VERSION 5.8 ;
BUSBITCHARS "[]" ;
DIVIDERCHAR "/" ;
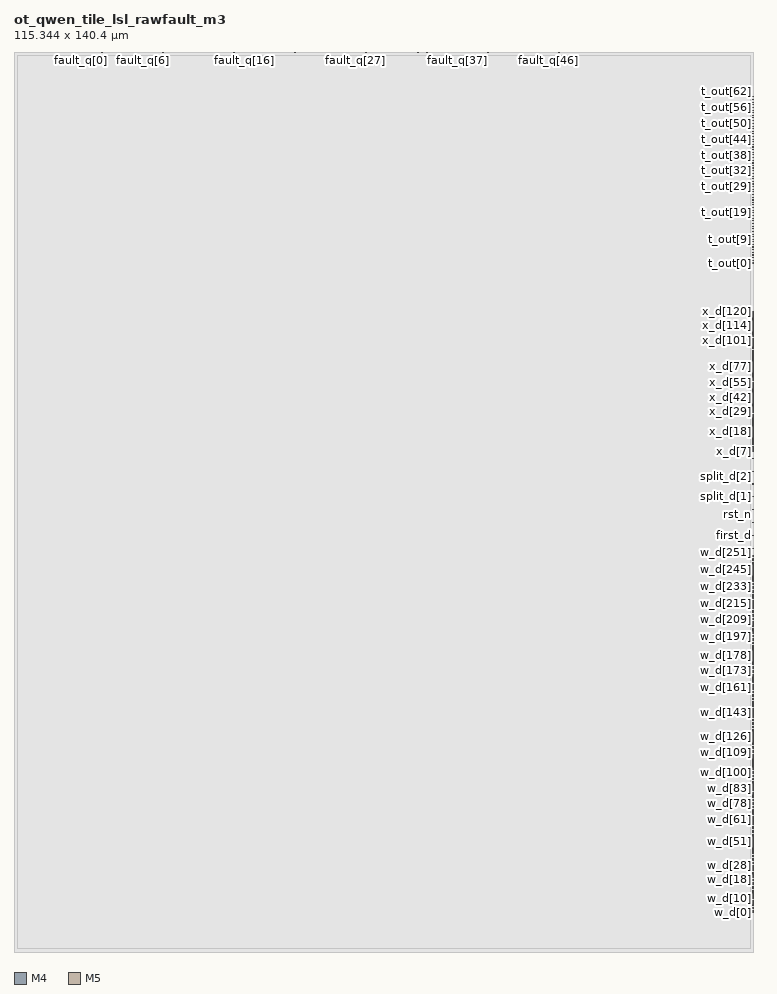
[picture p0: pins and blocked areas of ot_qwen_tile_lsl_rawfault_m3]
MACRO ot_qwen_tile_lsl_rawfault_m3
  CLASS BLOCK ;
  ORIGIN 0 0 ;
  SIZE 115.344 BY 140.4 ;
  SYMMETRY X Y ;
  PIN clk
    DIRECTION INPUT ;
    USE CLOCK ;
    PORT
      LAYER M4 ;
        RECT 115.2600 62.9760 115.3440 63.0000 ;
    END
  END clk
  PIN first_d
    DIRECTION INPUT ;
    USE SIGNAL ;
    PORT
      LAYER M4 ;
        RECT 115.2600 64.9920 115.3440 65.0160 ;
    END
  END first_d
  PIN rst_n
    DIRECTION INPUT ;
    USE SIGNAL ;
    PORT
      LAYER M4 ;
        RECT 115.2600 67.0080 115.3440 67.0320 ;
    END
  END rst_n
  PIN split_d[0]
    DIRECTION INPUT ;
    USE SIGNAL ;
    PORT
      LAYER M4 ;
        RECT 115.2600 68.9760 115.3440 69.0000 ;
    END
  END split_d[0]
  PIN split_d[1]
    DIRECTION INPUT ;
    USE SIGNAL ;
    PORT
      LAYER M4 ;
        RECT 115.2600 70.9920 115.3440 71.0160 ;
    END
  END split_d[1]
  PIN split_d[2]
    DIRECTION INPUT ;
    USE SIGNAL ;
    PORT
      LAYER M4 ;
        RECT 115.2600 73.0080 115.3440 73.0320 ;
    END
  END split_d[2]
  PIN split_d[3]
    DIRECTION INPUT ;
    USE SIGNAL ;
    PORT
      LAYER M4 ;
        RECT 115.2600 74.9760 115.3440 75.0000 ;
    END
  END split_d[3]
  PIN t_out[0]
    DIRECTION OUTPUT ;
    USE SIGNAL ;
    PORT
      LAYER M4 ;
        RECT 115.2600 107.4720 115.3440 107.4960 ;
    END
  END t_out[0]
  PIN t_out[10]
    DIRECTION OUTPUT ;
    USE SIGNAL ;
    PORT
      LAYER M4 ;
        RECT 115.2600 111.6000 115.3440 111.6240 ;
    END
  END t_out[10]
  PIN t_out[11]
    DIRECTION OUTPUT ;
    USE SIGNAL ;
    PORT
      LAYER M4 ;
        RECT 115.2600 111.9840 115.3440 112.0080 ;
    END
  END t_out[11]
  PIN t_out[12]
    DIRECTION OUTPUT ;
    USE SIGNAL ;
    PORT
      LAYER M4 ;
        RECT 115.2600 112.4160 115.3440 112.4400 ;
    END
  END t_out[12]
  PIN t_out[13]
    DIRECTION OUTPUT ;
    USE SIGNAL ;
    PORT
      LAYER M4 ;
        RECT 115.2600 112.8480 115.3440 112.8720 ;
    END
  END t_out[13]
  PIN t_out[14]
    DIRECTION OUTPUT ;
    USE SIGNAL ;
    PORT
      LAYER M4 ;
        RECT 115.2600 113.2320 115.3440 113.2560 ;
    END
  END t_out[14]
  PIN t_out[15]
    DIRECTION OUTPUT ;
    USE SIGNAL ;
    PORT
      LAYER M4 ;
        RECT 115.2600 113.6640 115.3440 113.6880 ;
    END
  END t_out[15]
  PIN t_out[16]
    DIRECTION OUTPUT ;
    USE SIGNAL ;
    PORT
      LAYER M4 ;
        RECT 115.2600 114.0480 115.3440 114.0720 ;
    END
  END t_out[16]
  PIN t_out[17]
    DIRECTION OUTPUT ;
    USE SIGNAL ;
    PORT
      LAYER M4 ;
        RECT 115.2600 114.4800 115.3440 114.5040 ;
    END
  END t_out[17]
  PIN t_out[18]
    DIRECTION OUTPUT ;
    USE SIGNAL ;
    PORT
      LAYER M4 ;
        RECT 115.2600 114.8640 115.3440 114.8880 ;
    END
  END t_out[18]
  PIN t_out[19]
    DIRECTION OUTPUT ;
    USE SIGNAL ;
    PORT
      LAYER M4 ;
        RECT 115.2600 115.2960 115.3440 115.3200 ;
    END
  END t_out[19]
  PIN t_out[1]
    DIRECTION OUTPUT ;
    USE SIGNAL ;
    PORT
      LAYER M4 ;
        RECT 115.2600 107.9040 115.3440 107.9280 ;
    END
  END t_out[1]
  PIN t_out[20]
    DIRECTION OUTPUT ;
    USE SIGNAL ;
    PORT
      LAYER M4 ;
        RECT 115.2600 115.6800 115.3440 115.7040 ;
    END
  END t_out[20]
  PIN t_out[21]
    DIRECTION OUTPUT ;
    USE SIGNAL ;
    PORT
      LAYER M4 ;
        RECT 115.2600 116.1120 115.3440 116.1360 ;
    END
  END t_out[21]
  PIN t_out[22]
    DIRECTION OUTPUT ;
    USE SIGNAL ;
    PORT
      LAYER M4 ;
        RECT 115.2600 116.5440 115.3440 116.5680 ;
    END
  END t_out[22]
  PIN t_out[23]
    DIRECTION OUTPUT ;
    USE SIGNAL ;
    PORT
      LAYER M4 ;
        RECT 115.2600 116.9280 115.3440 116.9520 ;
    END
  END t_out[23]
  PIN t_out[24]
    DIRECTION OUTPUT ;
    USE SIGNAL ;
    PORT
      LAYER M4 ;
        RECT 115.2600 117.3120 115.3440 117.3360 ;
    END
  END t_out[24]
  PIN t_out[25]
    DIRECTION OUTPUT ;
    USE SIGNAL ;
    PORT
      LAYER M4 ;
        RECT 115.2600 117.7440 115.3440 117.7680 ;
    END
  END t_out[25]
  PIN t_out[26]
    DIRECTION OUTPUT ;
    USE SIGNAL ;
    PORT
      LAYER M4 ;
        RECT 115.2600 118.1280 115.3440 118.1520 ;
    END
  END t_out[26]
  PIN t_out[27]
    DIRECTION OUTPUT ;
    USE SIGNAL ;
    PORT
      LAYER M4 ;
        RECT 115.2600 118.6080 115.3440 118.6320 ;
    END
  END t_out[27]
  PIN t_out[28]
    DIRECTION OUTPUT ;
    USE SIGNAL ;
    PORT
      LAYER M4 ;
        RECT 115.2600 118.9920 115.3440 119.0160 ;
    END
  END t_out[28]
  PIN t_out[29]
    DIRECTION OUTPUT ;
    USE SIGNAL ;
    PORT
      LAYER M4 ;
        RECT 115.2600 119.4240 115.3440 119.4480 ;
    END
  END t_out[29]
  PIN t_out[2]
    DIRECTION OUTPUT ;
    USE SIGNAL ;
    PORT
      LAYER M4 ;
        RECT 115.2600 108.2880 115.3440 108.3120 ;
    END
  END t_out[2]
  PIN t_out[30]
    DIRECTION OUTPUT ;
    USE SIGNAL ;
    PORT
      LAYER M4 ;
        RECT 115.2600 119.8080 115.3440 119.8320 ;
    END
  END t_out[30]
  PIN t_out[31]
    DIRECTION OUTPUT ;
    USE SIGNAL ;
    PORT
      LAYER M4 ;
        RECT 115.2600 120.1920 115.3440 120.2160 ;
    END
  END t_out[31]
  PIN t_out[32]
    DIRECTION OUTPUT ;
    USE SIGNAL ;
    PORT
      LAYER M4 ;
        RECT 115.2600 120.6240 115.3440 120.6480 ;
    END
  END t_out[32]
  PIN t_out[33]
    DIRECTION OUTPUT ;
    USE SIGNAL ;
    PORT
      LAYER M4 ;
        RECT 115.2600 121.0080 115.3440 121.0320 ;
    END
  END t_out[33]
  PIN t_out[34]
    DIRECTION OUTPUT ;
    USE SIGNAL ;
    PORT
      LAYER M4 ;
        RECT 115.2600 121.4880 115.3440 121.5120 ;
    END
  END t_out[34]
  PIN t_out[35]
    DIRECTION OUTPUT ;
    USE SIGNAL ;
    PORT
      LAYER M4 ;
        RECT 115.2600 121.8720 115.3440 121.8960 ;
    END
  END t_out[35]
  PIN t_out[36]
    DIRECTION OUTPUT ;
    USE SIGNAL ;
    PORT
      LAYER M4 ;
        RECT 115.2600 122.3040 115.3440 122.3280 ;
    END
  END t_out[36]
  PIN t_out[37]
    DIRECTION OUTPUT ;
    USE SIGNAL ;
    PORT
      LAYER M4 ;
        RECT 115.2600 122.6880 115.3440 122.7120 ;
    END
  END t_out[37]
  PIN t_out[38]
    DIRECTION OUTPUT ;
    USE SIGNAL ;
    PORT
      LAYER M4 ;
        RECT 115.2600 123.0720 115.3440 123.0960 ;
    END
  END t_out[38]
  PIN t_out[39]
    DIRECTION OUTPUT ;
    USE SIGNAL ;
    PORT
      LAYER M4 ;
        RECT 115.2600 123.5040 115.3440 123.5280 ;
    END
  END t_out[39]
  PIN t_out[3]
    DIRECTION OUTPUT ;
    USE SIGNAL ;
    PORT
      LAYER M4 ;
        RECT 115.2600 108.7200 115.3440 108.7440 ;
    END
  END t_out[3]
  PIN t_out[40]
    DIRECTION OUTPUT ;
    USE SIGNAL ;
    PORT
      LAYER M4 ;
        RECT 115.2600 123.8880 115.3440 123.9120 ;
    END
  END t_out[40]
  PIN t_out[41]
    DIRECTION OUTPUT ;
    USE SIGNAL ;
    PORT
      LAYER M4 ;
        RECT 115.2600 124.3680 115.3440 124.3920 ;
    END
  END t_out[41]
  PIN t_out[42]
    DIRECTION OUTPUT ;
    USE SIGNAL ;
    PORT
      LAYER M4 ;
        RECT 115.2600 124.7520 115.3440 124.7760 ;
    END
  END t_out[42]
  PIN t_out[43]
    DIRECTION OUTPUT ;
    USE SIGNAL ;
    PORT
      LAYER M4 ;
        RECT 115.2600 125.1360 115.3440 125.1600 ;
    END
  END t_out[43]
  PIN t_out[44]
    DIRECTION OUTPUT ;
    USE SIGNAL ;
    PORT
      LAYER M4 ;
        RECT 115.2600 125.5680 115.3440 125.5920 ;
    END
  END t_out[44]
  PIN t_out[45]
    DIRECTION OUTPUT ;
    USE SIGNAL ;
    PORT
      LAYER M4 ;
        RECT 115.2600 125.9520 115.3440 125.9760 ;
    END
  END t_out[45]
  PIN t_out[46]
    DIRECTION OUTPUT ;
    USE SIGNAL ;
    PORT
      LAYER M4 ;
        RECT 115.2600 126.3840 115.3440 126.4080 ;
    END
  END t_out[46]
  PIN t_out[47]
    DIRECTION OUTPUT ;
    USE SIGNAL ;
    PORT
      LAYER M4 ;
        RECT 115.2600 126.7680 115.3440 126.7920 ;
    END
  END t_out[47]
  PIN t_out[48]
    DIRECTION OUTPUT ;
    USE SIGNAL ;
    PORT
      LAYER M4 ;
        RECT 115.2600 127.2480 115.3440 127.2720 ;
    END
  END t_out[48]
  PIN t_out[49]
    DIRECTION OUTPUT ;
    USE SIGNAL ;
    PORT
      LAYER M4 ;
        RECT 115.2600 127.6320 115.3440 127.6560 ;
    END
  END t_out[49]
  PIN t_out[4]
    DIRECTION OUTPUT ;
    USE SIGNAL ;
    PORT
      LAYER M4 ;
        RECT 115.2600 109.1040 115.3440 109.1280 ;
    END
  END t_out[4]
  PIN t_out[50]
    DIRECTION OUTPUT ;
    USE SIGNAL ;
    PORT
      LAYER M4 ;
        RECT 115.2600 128.0160 115.3440 128.0400 ;
    END
  END t_out[50]
  PIN t_out[51]
    DIRECTION OUTPUT ;
    USE SIGNAL ;
    PORT
      LAYER M4 ;
        RECT 115.2600 128.4480 115.3440 128.4720 ;
    END
  END t_out[51]
  PIN t_out[52]
    DIRECTION OUTPUT ;
    USE SIGNAL ;
    PORT
      LAYER M4 ;
        RECT 115.2600 128.8320 115.3440 128.8560 ;
    END
  END t_out[52]
  PIN t_out[53]
    DIRECTION OUTPUT ;
    USE SIGNAL ;
    PORT
      LAYER M4 ;
        RECT 115.2600 129.2640 115.3440 129.2880 ;
    END
  END t_out[53]
  PIN t_out[54]
    DIRECTION OUTPUT ;
    USE SIGNAL ;
    PORT
      LAYER M4 ;
        RECT 115.2600 129.6480 115.3440 129.6720 ;
    END
  END t_out[54]
  PIN t_out[55]
    DIRECTION OUTPUT ;
    USE SIGNAL ;
    PORT
      LAYER M4 ;
        RECT 115.2600 130.1280 115.3440 130.1520 ;
    END
  END t_out[55]
  PIN t_out[56]
    DIRECTION OUTPUT ;
    USE SIGNAL ;
    PORT
      LAYER M4 ;
        RECT 115.2600 130.5120 115.3440 130.5360 ;
    END
  END t_out[56]
  PIN t_out[57]
    DIRECTION OUTPUT ;
    USE SIGNAL ;
    PORT
      LAYER M4 ;
        RECT 115.2600 130.8960 115.3440 130.9200 ;
    END
  END t_out[57]
  PIN t_out[58]
    DIRECTION OUTPUT ;
    USE SIGNAL ;
    PORT
      LAYER M4 ;
        RECT 115.2600 131.3280 115.3440 131.3520 ;
    END
  END t_out[58]
  PIN t_out[59]
    DIRECTION OUTPUT ;
    USE SIGNAL ;
    PORT
      LAYER M4 ;
        RECT 115.2600 131.7120 115.3440 131.7360 ;
    END
  END t_out[59]
  PIN t_out[5]
    DIRECTION OUTPUT ;
    USE SIGNAL ;
    PORT
      LAYER M4 ;
        RECT 115.2600 109.5360 115.3440 109.5600 ;
    END
  END t_out[5]
  PIN t_out[60]
    DIRECTION OUTPUT ;
    USE SIGNAL ;
    PORT
      LAYER M4 ;
        RECT 115.2600 132.1440 115.3440 132.1680 ;
    END
  END t_out[60]
  PIN t_out[61]
    DIRECTION OUTPUT ;
    USE SIGNAL ;
    PORT
      LAYER M4 ;
        RECT 115.2600 132.5280 115.3440 132.5520 ;
    END
  END t_out[61]
  PIN t_out[62]
    DIRECTION OUTPUT ;
    USE SIGNAL ;
    PORT
      LAYER M4 ;
        RECT 115.2600 132.9600 115.3440 132.9840 ;
    END
  END t_out[62]
  PIN t_out[63]
    DIRECTION OUTPUT ;
    USE SIGNAL ;
    PORT
      LAYER M4 ;
        RECT 115.2600 133.3920 115.3440 133.4160 ;
    END
  END t_out[63]
  PIN t_out[6]
    DIRECTION OUTPUT ;
    USE SIGNAL ;
    PORT
      LAYER M4 ;
        RECT 115.2600 109.9680 115.3440 109.9920 ;
    END
  END t_out[6]
  PIN t_out[7]
    DIRECTION OUTPUT ;
    USE SIGNAL ;
    PORT
      LAYER M4 ;
        RECT 115.2600 110.3520 115.3440 110.3760 ;
    END
  END t_out[7]
  PIN t_out[8]
    DIRECTION OUTPUT ;
    USE SIGNAL ;
    PORT
      LAYER M4 ;
        RECT 115.2600 110.7840 115.3440 110.8080 ;
    END
  END t_out[8]
  PIN t_out[9]
    DIRECTION OUTPUT ;
    USE SIGNAL ;
    PORT
      LAYER M4 ;
        RECT 115.2600 111.1680 115.3440 111.1920 ;
    END
  END t_out[9]
  PIN v_d
    DIRECTION INPUT ;
    USE SIGNAL ;
    PORT
      LAYER M4 ;
        RECT 115.2600 76.9920 115.3440 77.0160 ;
    END
  END v_d
  PIN w_d[0]
    DIRECTION INPUT ;
    USE SIGNAL ;
    PORT
      LAYER M4 ;
        RECT 115.2600 6.0960 115.3440 6.1200 ;
    END
  END w_d[0]
  PIN w_d[100]
    DIRECTION INPUT ;
    USE SIGNAL ;
    PORT
      LAYER M4 ;
        RECT 115.2600 27.9840 115.3440 28.0080 ;
    END
  END w_d[100]
  PIN w_d[101]
    DIRECTION INPUT ;
    USE SIGNAL ;
    PORT
      LAYER M4 ;
        RECT 115.2600 28.1760 115.3440 28.2000 ;
    END
  END w_d[101]
  PIN w_d[102]
    DIRECTION INPUT ;
    USE SIGNAL ;
    PORT
      LAYER M4 ;
        RECT 115.2600 28.4160 115.3440 28.4400 ;
    END
  END w_d[102]
  PIN w_d[103]
    DIRECTION INPUT ;
    USE SIGNAL ;
    PORT
      LAYER M4 ;
        RECT 115.2600 28.6080 115.3440 28.6320 ;
    END
  END w_d[103]
  PIN w_d[104]
    DIRECTION INPUT ;
    USE SIGNAL ;
    PORT
      LAYER M4 ;
        RECT 115.2600 28.8480 115.3440 28.8720 ;
    END
  END w_d[104]
  PIN w_d[105]
    DIRECTION INPUT ;
    USE SIGNAL ;
    PORT
      LAYER M4 ;
        RECT 115.2600 29.0400 115.3440 29.0640 ;
    END
  END w_d[105]
  PIN w_d[106]
    DIRECTION INPUT ;
    USE SIGNAL ;
    PORT
      LAYER M4 ;
        RECT 115.2600 29.3280 115.3440 29.3520 ;
    END
  END w_d[106]
  PIN w_d[107]
    DIRECTION INPUT ;
    USE SIGNAL ;
    PORT
      LAYER M4 ;
        RECT 115.2600 29.5200 115.3440 29.5440 ;
    END
  END w_d[107]
  PIN w_d[108]
    DIRECTION INPUT ;
    USE SIGNAL ;
    PORT
      LAYER M4 ;
        RECT 115.2600 29.7120 115.3440 29.7360 ;
    END
  END w_d[108]
  PIN w_d[109]
    DIRECTION INPUT ;
    USE SIGNAL ;
    PORT
      LAYER M4 ;
        RECT 115.2600 29.9520 115.3440 29.9760 ;
    END
  END w_d[109]
  PIN w_d[10]
    DIRECTION INPUT ;
    USE SIGNAL ;
    PORT
      LAYER M4 ;
        RECT 115.2600 8.3040 115.3440 8.3280 ;
    END
  END w_d[10]
  PIN w_d[110]
    DIRECTION INPUT ;
    USE SIGNAL ;
    PORT
      LAYER M4 ;
        RECT 115.2600 30.1440 115.3440 30.1680 ;
    END
  END w_d[110]
  PIN w_d[111]
    DIRECTION INPUT ;
    USE SIGNAL ;
    PORT
      LAYER M4 ;
        RECT 115.2600 30.3840 115.3440 30.4080 ;
    END
  END w_d[111]
  PIN w_d[112]
    DIRECTION INPUT ;
    USE SIGNAL ;
    PORT
      LAYER M4 ;
        RECT 115.2600 30.5760 115.3440 30.6000 ;
    END
  END w_d[112]
  PIN w_d[113]
    DIRECTION INPUT ;
    USE SIGNAL ;
    PORT
      LAYER M4 ;
        RECT 115.2600 30.7680 115.3440 30.7920 ;
    END
  END w_d[113]
  PIN w_d[114]
    DIRECTION INPUT ;
    USE SIGNAL ;
    PORT
      LAYER M4 ;
        RECT 115.2600 31.0560 115.3440 31.0800 ;
    END
  END w_d[114]
  PIN w_d[115]
    DIRECTION INPUT ;
    USE SIGNAL ;
    PORT
      LAYER M4 ;
        RECT 115.2600 31.2480 115.3440 31.2720 ;
    END
  END w_d[115]
  PIN w_d[116]
    DIRECTION INPUT ;
    USE SIGNAL ;
    PORT
      LAYER M4 ;
        RECT 115.2600 31.4880 115.3440 31.5120 ;
    END
  END w_d[116]
  PIN w_d[117]
    DIRECTION INPUT ;
    USE SIGNAL ;
    PORT
      LAYER M4 ;
        RECT 115.2600 31.6800 115.3440 31.7040 ;
    END
  END w_d[117]
  PIN w_d[118]
    DIRECTION INPUT ;
    USE SIGNAL ;
    PORT
      LAYER M4 ;
        RECT 115.2600 31.9200 115.3440 31.9440 ;
    END
  END w_d[118]
  PIN w_d[119]
    DIRECTION INPUT ;
    USE SIGNAL ;
    PORT
      LAYER M4 ;
        RECT 115.2600 32.1120 115.3440 32.1360 ;
    END
  END w_d[119]
  PIN w_d[11]
    DIRECTION INPUT ;
    USE SIGNAL ;
    PORT
      LAYER M4 ;
        RECT 115.2600 8.4960 115.3440 8.5200 ;
    END
  END w_d[11]
  PIN w_d[120]
    DIRECTION INPUT ;
    USE SIGNAL ;
    PORT
      LAYER M4 ;
        RECT 115.2600 32.3040 115.3440 32.3280 ;
    END
  END w_d[120]
  PIN w_d[121]
    DIRECTION INPUT ;
    USE SIGNAL ;
    PORT
      LAYER M4 ;
        RECT 115.2600 32.5920 115.3440 32.6160 ;
    END
  END w_d[121]
  PIN w_d[122]
    DIRECTION INPUT ;
    USE SIGNAL ;
    PORT
      LAYER M4 ;
        RECT 115.2600 32.7840 115.3440 32.8080 ;
    END
  END w_d[122]
  PIN w_d[123]
    DIRECTION INPUT ;
    USE SIGNAL ;
    PORT
      LAYER M4 ;
        RECT 115.2600 33.0240 115.3440 33.0480 ;
    END
  END w_d[123]
  PIN w_d[124]
    DIRECTION INPUT ;
    USE SIGNAL ;
    PORT
      LAYER M4 ;
        RECT 115.2600 33.2160 115.3440 33.2400 ;
    END
  END w_d[124]
  PIN w_d[125]
    DIRECTION INPUT ;
    USE SIGNAL ;
    PORT
      LAYER M4 ;
        RECT 115.2600 33.4080 115.3440 33.4320 ;
    END
  END w_d[125]
  PIN w_d[126]
    DIRECTION INPUT ;
    USE SIGNAL ;
    PORT
      LAYER M4 ;
        RECT 115.2600 33.6480 115.3440 33.6720 ;
    END
  END w_d[126]
  PIN w_d[127]
    DIRECTION INPUT ;
    USE SIGNAL ;
    PORT
      LAYER M4 ;
        RECT 115.2600 33.8400 115.3440 33.8640 ;
    END
  END w_d[127]
  PIN w_d[128]
    DIRECTION INPUT ;
    USE SIGNAL ;
    PORT
      LAYER M4 ;
        RECT 115.2600 34.0800 115.3440 34.1040 ;
    END
  END w_d[128]
  PIN w_d[129]
    DIRECTION INPUT ;
    USE SIGNAL ;
    PORT
      LAYER M4 ;
        RECT 115.2600 34.3200 115.3440 34.3440 ;
    END
  END w_d[129]
  PIN w_d[12]
    DIRECTION INPUT ;
    USE SIGNAL ;
    PORT
      LAYER M4 ;
        RECT 115.2600 8.7360 115.3440 8.7600 ;
    END
  END w_d[12]
  PIN w_d[130]
    DIRECTION INPUT ;
    USE SIGNAL ;
    PORT
      LAYER M4 ;
        RECT 115.2600 34.5120 115.3440 34.5360 ;
    END
  END w_d[130]
  PIN w_d[131]
    DIRECTION INPUT ;
    USE SIGNAL ;
    PORT
      LAYER M4 ;
        RECT 115.2600 34.7520 115.3440 34.7760 ;
    END
  END w_d[131]
  PIN w_d[132]
    DIRECTION INPUT ;
    USE SIGNAL ;
    PORT
      LAYER M4 ;
        RECT 115.2600 34.9920 115.3440 35.0160 ;
    END
  END w_d[132]
  PIN w_d[133]
    DIRECTION INPUT ;
    USE SIGNAL ;
    PORT
      LAYER M4 ;
        RECT 115.2600 35.1840 115.3440 35.2080 ;
    END
  END w_d[133]
  PIN w_d[134]
    DIRECTION INPUT ;
    USE SIGNAL ;
    PORT
      LAYER M4 ;
        RECT 115.2600 35.4240 115.3440 35.4480 ;
    END
  END w_d[134]
  PIN w_d[135]
    DIRECTION INPUT ;
    USE SIGNAL ;
    PORT
      LAYER M4 ;
        RECT 115.2600 35.6160 115.3440 35.6400 ;
    END
  END w_d[135]
  PIN w_d[136]
    DIRECTION INPUT ;
    USE SIGNAL ;
    PORT
      LAYER M4 ;
        RECT 115.2600 35.8560 115.3440 35.8800 ;
    END
  END w_d[136]
  PIN w_d[137]
    DIRECTION INPUT ;
    USE SIGNAL ;
    PORT
      LAYER M4 ;
        RECT 115.2600 36.0480 115.3440 36.0720 ;
    END
  END w_d[137]
  PIN w_d[138]
    DIRECTION INPUT ;
    USE SIGNAL ;
    PORT
      LAYER M4 ;
        RECT 115.2600 36.2880 115.3440 36.3120 ;
    END
  END w_d[138]
  PIN w_d[139]
    DIRECTION INPUT ;
    USE SIGNAL ;
    PORT
      LAYER M4 ;
        RECT 115.2600 36.5280 115.3440 36.5520 ;
    END
  END w_d[139]
  PIN w_d[13]
    DIRECTION INPUT ;
    USE SIGNAL ;
    PORT
      LAYER M4 ;
        RECT 115.2600 8.9280 115.3440 8.9520 ;
    END
  END w_d[13]
  PIN w_d[140]
    DIRECTION INPUT ;
    USE SIGNAL ;
    PORT
      LAYER M4 ;
        RECT 115.2600 36.7200 115.3440 36.7440 ;
    END
  END w_d[140]
  PIN w_d[141]
    DIRECTION INPUT ;
    USE SIGNAL ;
    PORT
      LAYER M4 ;
        RECT 115.2600 36.9600 115.3440 36.9840 ;
    END
  END w_d[141]
  PIN w_d[142]
    DIRECTION INPUT ;
    USE SIGNAL ;
    PORT
      LAYER M4 ;
        RECT 115.2600 37.1520 115.3440 37.1760 ;
    END
  END w_d[142]
  PIN w_d[143]
    DIRECTION INPUT ;
    USE SIGNAL ;
    PORT
      LAYER M4 ;
        RECT 115.2600 37.3920 115.3440 37.4160 ;
    END
  END w_d[143]
  PIN w_d[144]
    DIRECTION INPUT ;
    USE SIGNAL ;
    PORT
      LAYER M4 ;
        RECT 115.2600 37.5840 115.3440 37.6080 ;
    END
  END w_d[144]
  PIN w_d[145]
    DIRECTION INPUT ;
    USE SIGNAL ;
    PORT
      LAYER M4 ;
        RECT 115.2600 37.8240 115.3440 37.8480 ;
    END
  END w_d[145]
  PIN w_d[146]
    DIRECTION INPUT ;
    USE SIGNAL ;
    PORT
      LAYER M4 ;
        RECT 115.2600 38.0160 115.3440 38.0400 ;
    END
  END w_d[146]
  PIN w_d[147]
    DIRECTION INPUT ;
    USE SIGNAL ;
    PORT
      LAYER M4 ;
        RECT 115.2600 38.2560 115.3440 38.2800 ;
    END
  END w_d[147]
  PIN w_d[148]
    DIRECTION INPUT ;
    USE SIGNAL ;
    PORT
      LAYER M4 ;
        RECT 115.2600 38.4960 115.3440 38.5200 ;
    END
  END w_d[148]
  PIN w_d[149]
    DIRECTION INPUT ;
    USE SIGNAL ;
    PORT
      LAYER M4 ;
        RECT 115.2600 38.6880 115.3440 38.7120 ;
    END
  END w_d[149]
  PIN w_d[14]
    DIRECTION INPUT ;
    USE SIGNAL ;
    PORT
      LAYER M4 ;
        RECT 115.2600 9.1680 115.3440 9.1920 ;
    END
  END w_d[14]
  PIN w_d[150]
    DIRECTION INPUT ;
    USE SIGNAL ;
    PORT
      LAYER M4 ;
        RECT 115.2600 38.9280 115.3440 38.9520 ;
    END
  END w_d[150]
  PIN w_d[151]
    DIRECTION INPUT ;
    USE SIGNAL ;
    PORT
      LAYER M4 ;
        RECT 115.2600 39.1200 115.3440 39.1440 ;
    END
  END w_d[151]
  PIN w_d[152]
    DIRECTION INPUT ;
    USE SIGNAL ;
    PORT
      LAYER M4 ;
        RECT 115.2600 39.3600 115.3440 39.3840 ;
    END
  END w_d[152]
  PIN w_d[153]
    DIRECTION INPUT ;
    USE SIGNAL ;
    PORT
      LAYER M4 ;
        RECT 115.2600 39.5520 115.3440 39.5760 ;
    END
  END w_d[153]
  PIN w_d[154]
    DIRECTION INPUT ;
    USE SIGNAL ;
    PORT
      LAYER M4 ;
        RECT 115.2600 39.7920 115.3440 39.8160 ;
    END
  END w_d[154]
  PIN w_d[155]
    DIRECTION INPUT ;
    USE SIGNAL ;
    PORT
      LAYER M4 ;
        RECT 115.2600 39.9840 115.3440 40.0080 ;
    END
  END w_d[155]
  PIN w_d[156]
    DIRECTION INPUT ;
    USE SIGNAL ;
    PORT
      LAYER M4 ;
        RECT 115.2600 40.2240 115.3440 40.2480 ;
    END
  END w_d[156]
  PIN w_d[157]
    DIRECTION INPUT ;
    USE SIGNAL ;
    PORT
      LAYER M4 ;
        RECT 115.2600 40.4640 115.3440 40.4880 ;
    END
  END w_d[157]
  PIN w_d[158]
    DIRECTION INPUT ;
    USE SIGNAL ;
    PORT
      LAYER M4 ;
        RECT 115.2600 40.6560 115.3440 40.6800 ;
    END
  END w_d[158]
  PIN w_d[159]
    DIRECTION INPUT ;
    USE SIGNAL ;
    PORT
      LAYER M4 ;
        RECT 115.2600 40.8960 115.3440 40.9200 ;
    END
  END w_d[159]
  PIN w_d[15]
    DIRECTION INPUT ;
    USE SIGNAL ;
    PORT
      LAYER M4 ;
        RECT 115.2600 9.3600 115.3440 9.3840 ;
    END
  END w_d[15]
  PIN w_d[160]
    DIRECTION INPUT ;
    USE SIGNAL ;
    PORT
      LAYER M4 ;
        RECT 115.2600 41.0880 115.3440 41.1120 ;
    END
  END w_d[160]
  PIN w_d[161]
    DIRECTION INPUT ;
    USE SIGNAL ;
    PORT
      LAYER M4 ;
        RECT 115.2600 41.3280 115.3440 41.3520 ;
    END
  END w_d[161]
  PIN w_d[162]
    DIRECTION INPUT ;
    USE SIGNAL ;
    PORT
      LAYER M4 ;
        RECT 115.2600 41.5200 115.3440 41.5440 ;
    END
  END w_d[162]
  PIN w_d[163]
    DIRECTION INPUT ;
    USE SIGNAL ;
    PORT
      LAYER M4 ;
        RECT 115.2600 41.7120 115.3440 41.7360 ;
    END
  END w_d[163]
  PIN w_d[164]
    DIRECTION INPUT ;
    USE SIGNAL ;
    PORT
      LAYER M4 ;
        RECT 115.2600 42.0000 115.3440 42.0240 ;
    END
  END w_d[164]
  PIN w_d[165]
    DIRECTION INPUT ;
    USE SIGNAL ;
    PORT
      LAYER M4 ;
        RECT 115.2600 42.1920 115.3440 42.2160 ;
    END
  END w_d[165]
  PIN w_d[166]
    DIRECTION INPUT ;
    USE SIGNAL ;
    PORT
      LAYER M4 ;
        RECT 115.2600 42.4320 115.3440 42.4560 ;
    END
  END w_d[166]
  PIN w_d[167]
    DIRECTION INPUT ;
    USE SIGNAL ;
    PORT
      LAYER M4 ;
        RECT 115.2600 42.6240 115.3440 42.6480 ;
    END
  END w_d[167]
  PIN w_d[168]
    DIRECTION INPUT ;
    USE SIGNAL ;
    PORT
      LAYER M4 ;
        RECT 115.2600 42.8160 115.3440 42.8400 ;
    END
  END w_d[168]
  PIN w_d[169]
    DIRECTION INPUT ;
    USE SIGNAL ;
    PORT
      LAYER M4 ;
        RECT 115.2600 43.0560 115.3440 43.0800 ;
    END
  END w_d[169]
  PIN w_d[16]
    DIRECTION INPUT ;
    USE SIGNAL ;
    PORT
      LAYER M4 ;
        RECT 115.2600 9.6000 115.3440 9.6240 ;
    END
  END w_d[16]
  PIN w_d[170]
    DIRECTION INPUT ;
    USE SIGNAL ;
    PORT
      LAYER M4 ;
        RECT 115.2600 43.2480 115.3440 43.2720 ;
    END
  END w_d[170]
  PIN w_d[171]
    DIRECTION INPUT ;
    USE SIGNAL ;
    PORT
      LAYER M4 ;
        RECT 115.2600 43.5360 115.3440 43.5600 ;
    END
  END w_d[171]
  PIN w_d[172]
    DIRECTION INPUT ;
    USE SIGNAL ;
    PORT
      LAYER M4 ;
        RECT 115.2600 43.7280 115.3440 43.7520 ;
    END
  END w_d[172]
  PIN w_d[173]
    DIRECTION INPUT ;
    USE SIGNAL ;
    PORT
      LAYER M4 ;
        RECT 115.2600 43.9680 115.3440 43.9920 ;
    END
  END w_d[173]
  PIN w_d[174]
    DIRECTION INPUT ;
    USE SIGNAL ;
    PORT
      LAYER M4 ;
        RECT 115.2600 44.1600 115.3440 44.1840 ;
    END
  END w_d[174]
  PIN w_d[175]
    DIRECTION INPUT ;
    USE SIGNAL ;
    PORT
      LAYER M4 ;
        RECT 115.2600 44.3520 115.3440 44.3760 ;
    END
  END w_d[175]
  PIN w_d[176]
    DIRECTION INPUT ;
    USE SIGNAL ;
    PORT
      LAYER M4 ;
        RECT 115.2600 44.5920 115.3440 44.6160 ;
    END
  END w_d[176]
  PIN w_d[177]
    DIRECTION INPUT ;
    USE SIGNAL ;
    PORT
      LAYER M4 ;
        RECT 115.2600 44.7840 115.3440 44.8080 ;
    END
  END w_d[177]
  PIN w_d[178]
    DIRECTION INPUT ;
    USE SIGNAL ;
    PORT
      LAYER M4 ;
        RECT 115.2600 45.0720 115.3440 45.0960 ;
    END
  END w_d[178]
  PIN w_d[179]
    DIRECTION INPUT ;
    USE SIGNAL ;
    PORT
      LAYER M4 ;
        RECT 115.2600 45.2640 115.3440 45.2880 ;
    END
  END w_d[179]
  PIN w_d[17]
    DIRECTION INPUT ;
    USE SIGNAL ;
    PORT
      LAYER M4 ;
        RECT 115.2600 9.8400 115.3440 9.8640 ;
    END
  END w_d[17]
  PIN w_d[180]
    DIRECTION INPUT ;
    USE SIGNAL ;
    PORT
      LAYER M4 ;
        RECT 115.2600 45.4560 115.3440 45.4800 ;
    END
  END w_d[180]
  PIN w_d[181]
    DIRECTION INPUT ;
    USE SIGNAL ;
    PORT
      LAYER M4 ;
        RECT 115.2600 45.6960 115.3440 45.7200 ;
    END
  END w_d[181]
  PIN w_d[182]
    DIRECTION INPUT ;
    USE SIGNAL ;
    PORT
      LAYER M4 ;
        RECT 115.2600 45.8880 115.3440 45.9120 ;
    END
  END w_d[182]
  PIN w_d[183]
    DIRECTION INPUT ;
    USE SIGNAL ;
    PORT
      LAYER M4 ;
        RECT 115.2600 46.1280 115.3440 46.1520 ;
    END
  END w_d[183]
  PIN w_d[184]
    DIRECTION INPUT ;
    USE SIGNAL ;
    PORT
      LAYER M4 ;
        RECT 115.2600 46.3200 115.3440 46.3440 ;
    END
  END w_d[184]
  PIN w_d[185]
    DIRECTION INPUT ;
    USE SIGNAL ;
    PORT
      LAYER M4 ;
        RECT 115.2600 46.6080 115.3440 46.6320 ;
    END
  END w_d[185]
  PIN w_d[186]
    DIRECTION INPUT ;
    USE SIGNAL ;
    PORT
      LAYER M4 ;
        RECT 115.2600 46.8000 115.3440 46.8240 ;
    END
  END w_d[186]
  PIN w_d[187]
    DIRECTION INPUT ;
    USE SIGNAL ;
    PORT
      LAYER M4 ;
        RECT 115.2600 46.9920 115.3440 47.0160 ;
    END
  END w_d[187]
  PIN w_d[188]
    DIRECTION INPUT ;
    USE SIGNAL ;
    PORT
      LAYER M4 ;
        RECT 115.2600 47.2320 115.3440 47.2560 ;
    END
  END w_d[188]
  PIN w_d[189]
    DIRECTION INPUT ;
    USE SIGNAL ;
    PORT
      LAYER M4 ;
        RECT 115.2600 47.4240 115.3440 47.4480 ;
    END
  END w_d[189]
  PIN w_d[18]
    DIRECTION INPUT ;
    USE SIGNAL ;
    PORT
      LAYER M4 ;
        RECT 115.2600 10.0320 115.3440 10.0560 ;
    END
  END w_d[18]
  PIN w_d[190]
    DIRECTION INPUT ;
    USE SIGNAL ;
    PORT
      LAYER M4 ;
        RECT 115.2600 47.6640 115.3440 47.6880 ;
    END
  END w_d[190]
  PIN w_d[191]
    DIRECTION INPUT ;
    USE SIGNAL ;
    PORT
      LAYER M4 ;
        RECT 115.2600 47.8560 115.3440 47.8800 ;
    END
  END w_d[191]
  PIN w_d[192]
    DIRECTION INPUT ;
    USE SIGNAL ;
    PORT
      LAYER M4 ;
        RECT 115.2600 48.0960 115.3440 48.1200 ;
    END
  END w_d[192]
  PIN w_d[193]
    DIRECTION INPUT ;
    USE SIGNAL ;
    PORT
      LAYER M4 ;
        RECT 115.2600 48.3360 115.3440 48.3600 ;
    END
  END w_d[193]
  PIN w_d[194]
    DIRECTION INPUT ;
    USE SIGNAL ;
    PORT
      LAYER M4 ;
        RECT 115.2600 48.5280 115.3440 48.5520 ;
    END
  END w_d[194]
  PIN w_d[195]
    DIRECTION INPUT ;
    USE SIGNAL ;
    PORT
      LAYER M4 ;
        RECT 115.2600 48.7680 115.3440 48.7920 ;
    END
  END w_d[195]
  PIN w_d[196]
    DIRECTION INPUT ;
    USE SIGNAL ;
    PORT
      LAYER M4 ;
        RECT 115.2600 48.9600 115.3440 48.9840 ;
    END
  END w_d[196]
  PIN w_d[197]
    DIRECTION INPUT ;
    USE SIGNAL ;
    PORT
      LAYER M4 ;
        RECT 115.2600 49.2000 115.3440 49.2240 ;
    END
  END w_d[197]
  PIN w_d[198]
    DIRECTION INPUT ;
    USE SIGNAL ;
    PORT
      LAYER M4 ;
        RECT 115.2600 49.3920 115.3440 49.4160 ;
    END
  END w_d[198]
  PIN w_d[199]
    DIRECTION INPUT ;
    USE SIGNAL ;
    PORT
      LAYER M4 ;
        RECT 115.2600 49.6320 115.3440 49.6560 ;
    END
  END w_d[199]
  PIN w_d[19]
    DIRECTION INPUT ;
    USE SIGNAL ;
    PORT
      LAYER M4 ;
        RECT 115.2600 10.2720 115.3440 10.2960 ;
    END
  END w_d[19]
  PIN w_d[1]
    DIRECTION INPUT ;
    USE SIGNAL ;
    PORT
      LAYER M4 ;
        RECT 115.2600 6.3360 115.3440 6.3600 ;
    END
  END w_d[1]
  PIN w_d[200]
    DIRECTION INPUT ;
    USE SIGNAL ;
    PORT
      LAYER M4 ;
        RECT 115.2600 49.8240 115.3440 49.8480 ;
    END
  END w_d[200]
  PIN w_d[201]
    DIRECTION INPUT ;
    USE SIGNAL ;
    PORT
      LAYER M4 ;
        RECT 115.2600 50.0640 115.3440 50.0880 ;
    END
  END w_d[201]
  PIN w_d[202]
    DIRECTION INPUT ;
    USE SIGNAL ;
    PORT
      LAYER M4 ;
        RECT 115.2600 50.3040 115.3440 50.3280 ;
    END
  END w_d[202]
  PIN w_d[203]
    DIRECTION INPUT ;
    USE SIGNAL ;
    PORT
      LAYER M4 ;
        RECT 115.2600 50.4960 115.3440 50.5200 ;
    END
  END w_d[203]
  PIN w_d[204]
    DIRECTION INPUT ;
    USE SIGNAL ;
    PORT
      LAYER M4 ;
        RECT 115.2600 50.7360 115.3440 50.7600 ;
    END
  END w_d[204]
  PIN w_d[205]
    DIRECTION INPUT ;
    USE SIGNAL ;
    PORT
      LAYER M4 ;
        RECT 115.2600 50.9280 115.3440 50.9520 ;
    END
  END w_d[205]
  PIN w_d[206]
    DIRECTION INPUT ;
    USE SIGNAL ;
    PORT
      LAYER M4 ;
        RECT 115.2600 51.1680 115.3440 51.1920 ;
    END
  END w_d[206]
  PIN w_d[207]
    DIRECTION INPUT ;
    USE SIGNAL ;
    PORT
      LAYER M4 ;
        RECT 115.2600 51.3600 115.3440 51.3840 ;
    END
  END w_d[207]
  PIN w_d[208]
    DIRECTION INPUT ;
    USE SIGNAL ;
    PORT
      LAYER M4 ;
        RECT 115.2600 51.6000 115.3440 51.6240 ;
    END
  END w_d[208]
  PIN w_d[209]
    DIRECTION INPUT ;
    USE SIGNAL ;
    PORT
      LAYER M4 ;
        RECT 115.2600 51.8400 115.3440 51.8640 ;
    END
  END w_d[209]
  PIN w_d[20]
    DIRECTION INPUT ;
    USE SIGNAL ;
    PORT
      LAYER M4 ;
        RECT 115.2600 10.4640 115.3440 10.4880 ;
    END
  END w_d[20]
  PIN w_d[210]
    DIRECTION INPUT ;
    USE SIGNAL ;
    PORT
      LAYER M4 ;
        RECT 115.2600 52.0320 115.3440 52.0560 ;
    END
  END w_d[210]
  PIN w_d[211]
    DIRECTION INPUT ;
    USE SIGNAL ;
    PORT
      LAYER M4 ;
        RECT 115.2600 52.2720 115.3440 52.2960 ;
    END
  END w_d[211]
  PIN w_d[212]
    DIRECTION INPUT ;
    USE SIGNAL ;
    PORT
      LAYER M4 ;
        RECT 115.2600 52.4640 115.3440 52.4880 ;
    END
  END w_d[212]
  PIN w_d[213]
    DIRECTION INPUT ;
    USE SIGNAL ;
    PORT
      LAYER M4 ;
        RECT 115.2600 52.7040 115.3440 52.7280 ;
    END
  END w_d[213]
  PIN w_d[214]
    DIRECTION INPUT ;
    USE SIGNAL ;
    PORT
      LAYER M4 ;
        RECT 115.2600 52.8960 115.3440 52.9200 ;
    END
  END w_d[214]
  PIN w_d[215]
    DIRECTION INPUT ;
    USE SIGNAL ;
    PORT
      LAYER M4 ;
        RECT 115.2600 53.1360 115.3440 53.1600 ;
    END
  END w_d[215]
  PIN w_d[216]
    DIRECTION INPUT ;
    USE SIGNAL ;
    PORT
      LAYER M4 ;
        RECT 115.2600 53.3280 115.3440 53.3520 ;
    END
  END w_d[216]
  PIN w_d[217]
    DIRECTION INPUT ;
    USE SIGNAL ;
    PORT
      LAYER M4 ;
        RECT 115.2600 53.5680 115.3440 53.5920 ;
    END
  END w_d[217]
  PIN w_d[218]
    DIRECTION INPUT ;
    USE SIGNAL ;
    PORT
      LAYER M4 ;
        RECT 115.2600 53.8080 115.3440 53.8320 ;
    END
  END w_d[218]
  PIN w_d[219]
    DIRECTION INPUT ;
    USE SIGNAL ;
    PORT
      LAYER M4 ;
        RECT 115.2600 54.0000 115.3440 54.0240 ;
    END
  END w_d[219]
  PIN w_d[21]
    DIRECTION INPUT ;
    USE SIGNAL ;
    PORT
      LAYER M4 ;
        RECT 115.2600 10.7040 115.3440 10.7280 ;
    END
  END w_d[21]
  PIN w_d[220]
    DIRECTION INPUT ;
    USE SIGNAL ;
    PORT
      LAYER M4 ;
        RECT 115.2600 54.2400 115.3440 54.2640 ;
    END
  END w_d[220]
  PIN w_d[221]
    DIRECTION INPUT ;
    USE SIGNAL ;
    PORT
      LAYER M4 ;
        RECT 115.2600 54.4320 115.3440 54.4560 ;
    END
  END w_d[221]
  PIN w_d[222]
    DIRECTION INPUT ;
    USE SIGNAL ;
    PORT
      LAYER M4 ;
        RECT 115.2600 54.6720 115.3440 54.6960 ;
    END
  END w_d[222]
  PIN w_d[223]
    DIRECTION INPUT ;
    USE SIGNAL ;
    PORT
      LAYER M4 ;
        RECT 115.2600 54.8640 115.3440 54.8880 ;
    END
  END w_d[223]
  PIN w_d[224]
    DIRECTION INPUT ;
    USE SIGNAL ;
    PORT
      LAYER M4 ;
        RECT 115.2600 55.1040 115.3440 55.1280 ;
    END
  END w_d[224]
  PIN w_d[225]
    DIRECTION INPUT ;
    USE SIGNAL ;
    PORT
      LAYER M4 ;
        RECT 115.2600 55.2960 115.3440 55.3200 ;
    END
  END w_d[225]
  PIN w_d[226]
    DIRECTION INPUT ;
    USE SIGNAL ;
    PORT
      LAYER M4 ;
        RECT 115.2600 55.5360 115.3440 55.5600 ;
    END
  END w_d[226]
  PIN w_d[227]
    DIRECTION INPUT ;
    USE SIGNAL ;
    PORT
      LAYER M4 ;
        RECT 115.2600 55.7280 115.3440 55.7520 ;
    END
  END w_d[227]
  PIN w_d[228]
    DIRECTION INPUT ;
    USE SIGNAL ;
    PORT
      LAYER M4 ;
        RECT 115.2600 56.0160 115.3440 56.0400 ;
    END
  END w_d[228]
  PIN w_d[229]
    DIRECTION INPUT ;
    USE SIGNAL ;
    PORT
      LAYER M4 ;
        RECT 115.2600 56.2080 115.3440 56.2320 ;
    END
  END w_d[229]
  PIN w_d[22]
    DIRECTION INPUT ;
    USE SIGNAL ;
    PORT
      LAYER M4 ;
        RECT 115.2600 10.8960 115.3440 10.9200 ;
    END
  END w_d[22]
  PIN w_d[230]
    DIRECTION INPUT ;
    USE SIGNAL ;
    PORT
      LAYER M4 ;
        RECT 115.2600 56.4000 115.3440 56.4240 ;
    END
  END w_d[230]
  PIN w_d[231]
    DIRECTION INPUT ;
    USE SIGNAL ;
    PORT
      LAYER M4 ;
        RECT 115.2600 56.6400 115.3440 56.6640 ;
    END
  END w_d[231]
  PIN w_d[232]
    DIRECTION INPUT ;
    USE SIGNAL ;
    PORT
      LAYER M4 ;
        RECT 115.2600 56.8320 115.3440 56.8560 ;
    END
  END w_d[232]
  PIN w_d[233]
    DIRECTION INPUT ;
    USE SIGNAL ;
    PORT
      LAYER M4 ;
        RECT 115.2600 57.0720 115.3440 57.0960 ;
    END
  END w_d[233]
  PIN w_d[234]
    DIRECTION INPUT ;
    USE SIGNAL ;
    PORT
      LAYER M4 ;
        RECT 115.2600 57.2640 115.3440 57.2880 ;
    END
  END w_d[234]
  PIN w_d[235]
    DIRECTION INPUT ;
    USE SIGNAL ;
    PORT
      LAYER M4 ;
        RECT 115.2600 57.4560 115.3440 57.4800 ;
    END
  END w_d[235]
  PIN w_d[236]
    DIRECTION INPUT ;
    USE SIGNAL ;
    PORT
      LAYER M4 ;
        RECT 115.2600 57.7440 115.3440 57.7680 ;
    END
  END w_d[236]
  PIN w_d[237]
    DIRECTION INPUT ;
    USE SIGNAL ;
    PORT
      LAYER M4 ;
        RECT 115.2600 57.9360 115.3440 57.9600 ;
    END
  END w_d[237]
  PIN w_d[238]
    DIRECTION INPUT ;
    USE SIGNAL ;
    PORT
      LAYER M4 ;
        RECT 115.2600 58.1760 115.3440 58.2000 ;
    END
  END w_d[238]
  PIN w_d[239]
    DIRECTION INPUT ;
    USE SIGNAL ;
    PORT
      LAYER M4 ;
        RECT 115.2600 58.3680 115.3440 58.3920 ;
    END
  END w_d[239]
  PIN w_d[23]
    DIRECTION INPUT ;
    USE SIGNAL ;
    PORT
      LAYER M4 ;
        RECT 115.2600 11.1360 115.3440 11.1600 ;
    END
  END w_d[23]
  PIN w_d[240]
    DIRECTION INPUT ;
    USE SIGNAL ;
    PORT
      LAYER M4 ;
        RECT 115.2600 58.6080 115.3440 58.6320 ;
    END
  END w_d[240]
  PIN w_d[241]
    DIRECTION INPUT ;
    USE SIGNAL ;
    PORT
      LAYER M4 ;
        RECT 115.2600 58.8000 115.3440 58.8240 ;
    END
  END w_d[241]
  PIN w_d[242]
    DIRECTION INPUT ;
    USE SIGNAL ;
    PORT
      LAYER M4 ;
        RECT 115.2600 58.9920 115.3440 59.0160 ;
    END
  END w_d[242]
  PIN w_d[243]
    DIRECTION INPUT ;
    USE SIGNAL ;
    PORT
      LAYER M4 ;
        RECT 115.2600 59.2800 115.3440 59.3040 ;
    END
  END w_d[243]
  PIN w_d[244]
    DIRECTION INPUT ;
    USE SIGNAL ;
    PORT
      LAYER M4 ;
        RECT 115.2600 59.4720 115.3440 59.4960 ;
    END
  END w_d[244]
  PIN w_d[245]
    DIRECTION INPUT ;
    USE SIGNAL ;
    PORT
      LAYER M4 ;
        RECT 115.2600 59.7120 115.3440 59.7360 ;
    END
  END w_d[245]
  PIN w_d[246]
    DIRECTION INPUT ;
    USE SIGNAL ;
    PORT
      LAYER M4 ;
        RECT 115.2600 59.9040 115.3440 59.9280 ;
    END
  END w_d[246]
  PIN w_d[247]
    DIRECTION INPUT ;
    USE SIGNAL ;
    PORT
      LAYER M4 ;
        RECT 115.2600 60.0960 115.3440 60.1200 ;
    END
  END w_d[247]
  PIN w_d[248]
    DIRECTION INPUT ;
    USE SIGNAL ;
    PORT
      LAYER M4 ;
        RECT 115.2600 60.3360 115.3440 60.3600 ;
    END
  END w_d[248]
  PIN w_d[249]
    DIRECTION INPUT ;
    USE SIGNAL ;
    PORT
      LAYER M4 ;
        RECT 115.2600 60.5280 115.3440 60.5520 ;
    END
  END w_d[249]
  PIN w_d[24]
    DIRECTION INPUT ;
    USE SIGNAL ;
    PORT
      LAYER M4 ;
        RECT 115.2600 11.3280 115.3440 11.3520 ;
    END
  END w_d[24]
  PIN w_d[250]
    DIRECTION INPUT ;
    USE SIGNAL ;
    PORT
      LAYER M4 ;
        RECT 115.2600 60.8160 115.3440 60.8400 ;
    END
  END w_d[250]
  PIN w_d[251]
    DIRECTION INPUT ;
    USE SIGNAL ;
    PORT
      LAYER M4 ;
        RECT 115.2600 61.0080 115.3440 61.0320 ;
    END
  END w_d[251]
  PIN w_d[252]
    DIRECTION INPUT ;
    USE SIGNAL ;
    PORT
      LAYER M4 ;
        RECT 115.2600 61.2480 115.3440 61.2720 ;
    END
  END w_d[252]
  PIN w_d[253]
    DIRECTION INPUT ;
    USE SIGNAL ;
    PORT
      LAYER M4 ;
        RECT 115.2600 61.4400 115.3440 61.4640 ;
    END
  END w_d[253]
  PIN w_d[254]
    DIRECTION INPUT ;
    USE SIGNAL ;
    PORT
      LAYER M4 ;
        RECT 115.2600 61.6320 115.3440 61.6560 ;
    END
  END w_d[254]
  PIN w_d[255]
    DIRECTION INPUT ;
    USE SIGNAL ;
    PORT
      LAYER M4 ;
        RECT 115.2600 61.8720 115.3440 61.8960 ;
    END
  END w_d[255]
  PIN w_d[25]
    DIRECTION INPUT ;
    USE SIGNAL ;
    PORT
      LAYER M4 ;
        RECT 115.2600 11.5680 115.3440 11.5920 ;
    END
  END w_d[25]
  PIN w_d[26]
    DIRECTION INPUT ;
    USE SIGNAL ;
    PORT
      LAYER M4 ;
        RECT 115.2600 11.8080 115.3440 11.8320 ;
    END
  END w_d[26]
  PIN w_d[27]
    DIRECTION INPUT ;
    USE SIGNAL ;
    PORT
      LAYER M4 ;
        RECT 115.2600 12.0000 115.3440 12.0240 ;
    END
  END w_d[27]
  PIN w_d[28]
    DIRECTION INPUT ;
    USE SIGNAL ;
    PORT
      LAYER M4 ;
        RECT 115.2600 12.2400 115.3440 12.2640 ;
    END
  END w_d[28]
  PIN w_d[29]
    DIRECTION INPUT ;
    USE SIGNAL ;
    PORT
      LAYER M4 ;
        RECT 115.2600 12.4320 115.3440 12.4560 ;
    END
  END w_d[29]
  PIN w_d[2]
    DIRECTION INPUT ;
    USE SIGNAL ;
    PORT
      LAYER M4 ;
        RECT 115.2600 6.5280 115.3440 6.5520 ;
    END
  END w_d[2]
  PIN w_d[30]
    DIRECTION INPUT ;
    USE SIGNAL ;
    PORT
      LAYER M4 ;
        RECT 115.2600 12.6720 115.3440 12.6960 ;
    END
  END w_d[30]
  PIN w_d[31]
    DIRECTION INPUT ;
    USE SIGNAL ;
    PORT
      LAYER M4 ;
        RECT 115.2600 12.8640 115.3440 12.8880 ;
    END
  END w_d[31]
  PIN w_d[32]
    DIRECTION INPUT ;
    USE SIGNAL ;
    PORT
      LAYER M4 ;
        RECT 115.2600 13.1040 115.3440 13.1280 ;
    END
  END w_d[32]
  PIN w_d[33]
    DIRECTION INPUT ;
    USE SIGNAL ;
    PORT
      LAYER M4 ;
        RECT 115.2600 13.2960 115.3440 13.3200 ;
    END
  END w_d[33]
  PIN w_d[34]
    DIRECTION INPUT ;
    USE SIGNAL ;
    PORT
      LAYER M4 ;
        RECT 115.2600 13.4880 115.3440 13.5120 ;
    END
  END w_d[34]
  PIN w_d[35]
    DIRECTION INPUT ;
    USE SIGNAL ;
    PORT
      LAYER M4 ;
        RECT 115.2600 13.7760 115.3440 13.8000 ;
    END
  END w_d[35]
  PIN w_d[36]
    DIRECTION INPUT ;
    USE SIGNAL ;
    PORT
      LAYER M4 ;
        RECT 115.2600 13.9680 115.3440 13.9920 ;
    END
  END w_d[36]
  PIN w_d[37]
    DIRECTION INPUT ;
    USE SIGNAL ;
    PORT
      LAYER M4 ;
        RECT 115.2600 14.2080 115.3440 14.2320 ;
    END
  END w_d[37]
  PIN w_d[38]
    DIRECTION INPUT ;
    USE SIGNAL ;
    PORT
      LAYER M4 ;
        RECT 115.2600 14.4000 115.3440 14.4240 ;
    END
  END w_d[38]
  PIN w_d[39]
    DIRECTION INPUT ;
    USE SIGNAL ;
    PORT
      LAYER M4 ;
        RECT 115.2600 14.6400 115.3440 14.6640 ;
    END
  END w_d[39]
  PIN w_d[3]
    DIRECTION INPUT ;
    USE SIGNAL ;
    PORT
      LAYER M4 ;
        RECT 115.2600 6.7680 115.3440 6.7920 ;
    END
  END w_d[3]
  PIN w_d[40]
    DIRECTION INPUT ;
    USE SIGNAL ;
    PORT
      LAYER M4 ;
        RECT 115.2600 14.8320 115.3440 14.8560 ;
    END
  END w_d[40]
  PIN w_d[41]
    DIRECTION INPUT ;
    USE SIGNAL ;
    PORT
      LAYER M4 ;
        RECT 115.2600 15.0240 115.3440 15.0480 ;
    END
  END w_d[41]
  PIN w_d[42]
    DIRECTION INPUT ;
    USE SIGNAL ;
    PORT
      LAYER M4 ;
        RECT 115.2600 15.3120 115.3440 15.3360 ;
    END
  END w_d[42]
  PIN w_d[43]
    DIRECTION INPUT ;
    USE SIGNAL ;
    PORT
      LAYER M4 ;
        RECT 115.2600 15.5040 115.3440 15.5280 ;
    END
  END w_d[43]
  PIN w_d[44]
    DIRECTION INPUT ;
    USE SIGNAL ;
    PORT
      LAYER M4 ;
        RECT 115.2600 15.7440 115.3440 15.7680 ;
    END
  END w_d[44]
  PIN w_d[45]
    DIRECTION INPUT ;
    USE SIGNAL ;
    PORT
      LAYER M4 ;
        RECT 115.2600 15.9360 115.3440 15.9600 ;
    END
  END w_d[45]
  PIN w_d[46]
    DIRECTION INPUT ;
    USE SIGNAL ;
    PORT
      LAYER M4 ;
        RECT 115.2600 16.1280 115.3440 16.1520 ;
    END
  END w_d[46]
  PIN w_d[47]
    DIRECTION INPUT ;
    USE SIGNAL ;
    PORT
      LAYER M4 ;
        RECT 115.2600 16.3680 115.3440 16.3920 ;
    END
  END w_d[47]
  PIN w_d[48]
    DIRECTION INPUT ;
    USE SIGNAL ;
    PORT
      LAYER M4 ;
        RECT 115.2600 16.5600 115.3440 16.5840 ;
    END
  END w_d[48]
  PIN w_d[49]
    DIRECTION INPUT ;
    USE SIGNAL ;
    PORT
      LAYER M4 ;
        RECT 115.2600 16.8480 115.3440 16.8720 ;
    END
  END w_d[49]
  PIN w_d[4]
    DIRECTION INPUT ;
    USE SIGNAL ;
    PORT
      LAYER M4 ;
        RECT 115.2600 6.9600 115.3440 6.9840 ;
    END
  END w_d[4]
  PIN w_d[50]
    DIRECTION INPUT ;
    USE SIGNAL ;
    PORT
      LAYER M4 ;
        RECT 115.2600 17.0400 115.3440 17.0640 ;
    END
  END w_d[50]
  PIN w_d[51]
    DIRECTION INPUT ;
    USE SIGNAL ;
    PORT
      LAYER M4 ;
        RECT 115.2600 17.2800 115.3440 17.3040 ;
    END
  END w_d[51]
  PIN w_d[52]
    DIRECTION INPUT ;
    USE SIGNAL ;
    PORT
      LAYER M4 ;
        RECT 115.2600 17.4720 115.3440 17.4960 ;
    END
  END w_d[52]
  PIN w_d[53]
    DIRECTION INPUT ;
    USE SIGNAL ;
    PORT
      LAYER M4 ;
        RECT 115.2600 17.6640 115.3440 17.6880 ;
    END
  END w_d[53]
  PIN w_d[54]
    DIRECTION INPUT ;
    USE SIGNAL ;
    PORT
      LAYER M4 ;
        RECT 115.2600 17.9040 115.3440 17.9280 ;
    END
  END w_d[54]
  PIN w_d[55]
    DIRECTION INPUT ;
    USE SIGNAL ;
    PORT
      LAYER M4 ;
        RECT 115.2600 18.0960 115.3440 18.1200 ;
    END
  END w_d[55]
  PIN w_d[56]
    DIRECTION INPUT ;
    USE SIGNAL ;
    PORT
      LAYER M4 ;
        RECT 115.2600 18.3840 115.3440 18.4080 ;
    END
  END w_d[56]
  PIN w_d[57]
    DIRECTION INPUT ;
    USE SIGNAL ;
    PORT
      LAYER M4 ;
        RECT 115.2600 18.5760 115.3440 18.6000 ;
    END
  END w_d[57]
  PIN w_d[58]
    DIRECTION INPUT ;
    USE SIGNAL ;
    PORT
      LAYER M4 ;
        RECT 115.2600 18.7680 115.3440 18.7920 ;
    END
  END w_d[58]
  PIN w_d[59]
    DIRECTION INPUT ;
    USE SIGNAL ;
    PORT
      LAYER M4 ;
        RECT 115.2600 19.0080 115.3440 19.0320 ;
    END
  END w_d[59]
  PIN w_d[5]
    DIRECTION INPUT ;
    USE SIGNAL ;
    PORT
      LAYER M4 ;
        RECT 115.2600 7.2000 115.3440 7.2240 ;
    END
  END w_d[5]
  PIN w_d[60]
    DIRECTION INPUT ;
    USE SIGNAL ;
    PORT
      LAYER M4 ;
        RECT 115.2600 19.2000 115.3440 19.2240 ;
    END
  END w_d[60]
  PIN w_d[61]
    DIRECTION INPUT ;
    USE SIGNAL ;
    PORT
      LAYER M4 ;
        RECT 115.2600 19.4400 115.3440 19.4640 ;
    END
  END w_d[61]
  PIN w_d[62]
    DIRECTION INPUT ;
    USE SIGNAL ;
    PORT
      LAYER M4 ;
        RECT 115.2600 19.6320 115.3440 19.6560 ;
    END
  END w_d[62]
  PIN w_d[63]
    DIRECTION INPUT ;
    USE SIGNAL ;
    PORT
      LAYER M4 ;
        RECT 115.2600 19.9200 115.3440 19.9440 ;
    END
  END w_d[63]
  PIN w_d[64]
    DIRECTION INPUT ;
    USE SIGNAL ;
    PORT
      LAYER M4 ;
        RECT 115.2600 20.1120 115.3440 20.1360 ;
    END
  END w_d[64]
  PIN w_d[65]
    DIRECTION INPUT ;
    USE SIGNAL ;
    PORT
      LAYER M4 ;
        RECT 115.2600 20.3040 115.3440 20.3280 ;
    END
  END w_d[65]
  PIN w_d[66]
    DIRECTION INPUT ;
    USE SIGNAL ;
    PORT
      LAYER M4 ;
        RECT 115.2600 20.5440 115.3440 20.5680 ;
    END
  END w_d[66]
  PIN w_d[67]
    DIRECTION INPUT ;
    USE SIGNAL ;
    PORT
      LAYER M4 ;
        RECT 115.2600 20.7360 115.3440 20.7600 ;
    END
  END w_d[67]
  PIN w_d[68]
    DIRECTION INPUT ;
    USE SIGNAL ;
    PORT
      LAYER M4 ;
        RECT 115.2600 20.9760 115.3440 21.0000 ;
    END
  END w_d[68]
  PIN w_d[69]
    DIRECTION INPUT ;
    USE SIGNAL ;
    PORT
      LAYER M4 ;
        RECT 115.2600 21.1680 115.3440 21.1920 ;
    END
  END w_d[69]
  PIN w_d[6]
    DIRECTION INPUT ;
    USE SIGNAL ;
    PORT
      LAYER M4 ;
        RECT 115.2600 7.3920 115.3440 7.4160 ;
    END
  END w_d[6]
  PIN w_d[70]
    DIRECTION INPUT ;
    USE SIGNAL ;
    PORT
      LAYER M4 ;
        RECT 115.2600 21.4080 115.3440 21.4320 ;
    END
  END w_d[70]
  PIN w_d[71]
    DIRECTION INPUT ;
    USE SIGNAL ;
    PORT
      LAYER M4 ;
        RECT 115.2600 21.6480 115.3440 21.6720 ;
    END
  END w_d[71]
  PIN w_d[72]
    DIRECTION INPUT ;
    USE SIGNAL ;
    PORT
      LAYER M4 ;
        RECT 115.2600 21.8400 115.3440 21.8640 ;
    END
  END w_d[72]
  PIN w_d[73]
    DIRECTION INPUT ;
    USE SIGNAL ;
    PORT
      LAYER M4 ;
        RECT 115.2600 22.0800 115.3440 22.1040 ;
    END
  END w_d[73]
  PIN w_d[74]
    DIRECTION INPUT ;
    USE SIGNAL ;
    PORT
      LAYER M4 ;
        RECT 115.2600 22.2720 115.3440 22.2960 ;
    END
  END w_d[74]
  PIN w_d[75]
    DIRECTION INPUT ;
    USE SIGNAL ;
    PORT
      LAYER M4 ;
        RECT 115.2600 22.5120 115.3440 22.5360 ;
    END
  END w_d[75]
  PIN w_d[76]
    DIRECTION INPUT ;
    USE SIGNAL ;
    PORT
      LAYER M4 ;
        RECT 115.2600 22.7040 115.3440 22.7280 ;
    END
  END w_d[76]
  PIN w_d[77]
    DIRECTION INPUT ;
    USE SIGNAL ;
    PORT
      LAYER M4 ;
        RECT 115.2600 22.9440 115.3440 22.9680 ;
    END
  END w_d[77]
  PIN w_d[78]
    DIRECTION INPUT ;
    USE SIGNAL ;
    PORT
      LAYER M4 ;
        RECT 115.2600 23.1840 115.3440 23.2080 ;
    END
  END w_d[78]
  PIN w_d[79]
    DIRECTION INPUT ;
    USE SIGNAL ;
    PORT
      LAYER M4 ;
        RECT 115.2600 23.3760 115.3440 23.4000 ;
    END
  END w_d[79]
  PIN w_d[7]
    DIRECTION INPUT ;
    USE SIGNAL ;
    PORT
      LAYER M4 ;
        RECT 115.2600 7.6320 115.3440 7.6560 ;
    END
  END w_d[7]
  PIN w_d[80]
    DIRECTION INPUT ;
    USE SIGNAL ;
    PORT
      LAYER M4 ;
        RECT 115.2600 23.6160 115.3440 23.6400 ;
    END
  END w_d[80]
  PIN w_d[81]
    DIRECTION INPUT ;
    USE SIGNAL ;
    PORT
      LAYER M4 ;
        RECT 115.2600 23.8080 115.3440 23.8320 ;
    END
  END w_d[81]
  PIN w_d[82]
    DIRECTION INPUT ;
    USE SIGNAL ;
    PORT
      LAYER M4 ;
        RECT 115.2600 24.0480 115.3440 24.0720 ;
    END
  END w_d[82]
  PIN w_d[83]
    DIRECTION INPUT ;
    USE SIGNAL ;
    PORT
      LAYER M4 ;
        RECT 115.2600 24.2400 115.3440 24.2640 ;
    END
  END w_d[83]
  PIN w_d[84]
    DIRECTION INPUT ;
    USE SIGNAL ;
    PORT
      LAYER M4 ;
        RECT 115.2600 24.4800 115.3440 24.5040 ;
    END
  END w_d[84]
  PIN w_d[85]
    DIRECTION INPUT ;
    USE SIGNAL ;
    PORT
      LAYER M4 ;
        RECT 115.2600 24.6720 115.3440 24.6960 ;
    END
  END w_d[85]
  PIN w_d[86]
    DIRECTION INPUT ;
    USE SIGNAL ;
    PORT
      LAYER M4 ;
        RECT 115.2600 24.9120 115.3440 24.9360 ;
    END
  END w_d[86]
  PIN w_d[87]
    DIRECTION INPUT ;
    USE SIGNAL ;
    PORT
      LAYER M4 ;
        RECT 115.2600 25.1520 115.3440 25.1760 ;
    END
  END w_d[87]
  PIN w_d[88]
    DIRECTION INPUT ;
    USE SIGNAL ;
    PORT
      LAYER M4 ;
        RECT 115.2600 25.3440 115.3440 25.3680 ;
    END
  END w_d[88]
  PIN w_d[89]
    DIRECTION INPUT ;
    USE SIGNAL ;
    PORT
      LAYER M4 ;
        RECT 115.2600 25.5840 115.3440 25.6080 ;
    END
  END w_d[89]
  PIN w_d[8]
    DIRECTION INPUT ;
    USE SIGNAL ;
    PORT
      LAYER M4 ;
        RECT 115.2600 7.8240 115.3440 7.8480 ;
    END
  END w_d[8]
  PIN w_d[90]
    DIRECTION INPUT ;
    USE SIGNAL ;
    PORT
      LAYER M4 ;
        RECT 115.2600 25.7760 115.3440 25.8000 ;
    END
  END w_d[90]
  PIN w_d[91]
    DIRECTION INPUT ;
    USE SIGNAL ;
    PORT
      LAYER M4 ;
        RECT 115.2600 26.0160 115.3440 26.0400 ;
    END
  END w_d[91]
  PIN w_d[92]
    DIRECTION INPUT ;
    USE SIGNAL ;
    PORT
      LAYER M4 ;
        RECT 115.2600 26.2080 115.3440 26.2320 ;
    END
  END w_d[92]
  PIN w_d[93]
    DIRECTION INPUT ;
    USE SIGNAL ;
    PORT
      LAYER M4 ;
        RECT 115.2600 26.4480 115.3440 26.4720 ;
    END
  END w_d[93]
  PIN w_d[94]
    DIRECTION INPUT ;
    USE SIGNAL ;
    PORT
      LAYER M4 ;
        RECT 115.2600 26.6400 115.3440 26.6640 ;
    END
  END w_d[94]
  PIN w_d[95]
    DIRECTION INPUT ;
    USE SIGNAL ;
    PORT
      LAYER M4 ;
        RECT 115.2600 26.8800 115.3440 26.9040 ;
    END
  END w_d[95]
  PIN w_d[96]
    DIRECTION INPUT ;
    USE SIGNAL ;
    PORT
      LAYER M4 ;
        RECT 115.2600 27.0720 115.3440 27.0960 ;
    END
  END w_d[96]
  PIN w_d[97]
    DIRECTION INPUT ;
    USE SIGNAL ;
    PORT
      LAYER M4 ;
        RECT 115.2600 27.3120 115.3440 27.3360 ;
    END
  END w_d[97]
  PIN w_d[98]
    DIRECTION INPUT ;
    USE SIGNAL ;
    PORT
      LAYER M4 ;
        RECT 115.2600 27.5040 115.3440 27.5280 ;
    END
  END w_d[98]
  PIN w_d[99]
    DIRECTION INPUT ;
    USE SIGNAL ;
    PORT
      LAYER M4 ;
        RECT 115.2600 27.7920 115.3440 27.8160 ;
    END
  END w_d[99]
  PIN w_d[9]
    DIRECTION INPUT ;
    USE SIGNAL ;
    PORT
      LAYER M4 ;
        RECT 115.2600 8.0640 115.3440 8.0880 ;
    END
  END w_d[9]
  PIN x_d[0]
    DIRECTION INPUT ;
    USE SIGNAL ;
    PORT
      LAYER M4 ;
        RECT 115.2600 78.0960 115.3440 78.1200 ;
    END
  END x_d[0]
  PIN x_d[100]
    DIRECTION INPUT ;
    USE SIGNAL ;
    PORT
      LAYER M4 ;
        RECT 115.2600 95.2320 115.3440 95.2560 ;
    END
  END x_d[100]
  PIN x_d[101]
    DIRECTION INPUT ;
    USE SIGNAL ;
    PORT
      LAYER M4 ;
        RECT 115.2600 95.4240 115.3440 95.4480 ;
    END
  END x_d[101]
  PIN x_d[102]
    DIRECTION INPUT ;
    USE SIGNAL ;
    PORT
      LAYER M4 ;
        RECT 115.2600 95.6160 115.3440 95.6400 ;
    END
  END x_d[102]
  PIN x_d[103]
    DIRECTION INPUT ;
    USE SIGNAL ;
    PORT
      LAYER M4 ;
        RECT 115.2600 95.7600 115.3440 95.7840 ;
    END
  END x_d[103]
  PIN x_d[104]
    DIRECTION INPUT ;
    USE SIGNAL ;
    PORT
      LAYER M4 ;
        RECT 115.2600 95.9520 115.3440 95.9760 ;
    END
  END x_d[104]
  PIN x_d[105]
    DIRECTION INPUT ;
    USE SIGNAL ;
    PORT
      LAYER M4 ;
        RECT 115.2600 96.1440 115.3440 96.1680 ;
    END
  END x_d[105]
  PIN x_d[106]
    DIRECTION INPUT ;
    USE SIGNAL ;
    PORT
      LAYER M4 ;
        RECT 115.2600 96.3360 115.3440 96.3600 ;
    END
  END x_d[106]
  PIN x_d[107]
    DIRECTION INPUT ;
    USE SIGNAL ;
    PORT
      LAYER M4 ;
        RECT 115.2600 96.4320 115.3440 96.4560 ;
    END
  END x_d[107]
  PIN x_d[108]
    DIRECTION INPUT ;
    USE SIGNAL ;
    PORT
      LAYER M4 ;
        RECT 115.2600 96.6240 115.3440 96.6480 ;
    END
  END x_d[108]
  PIN x_d[109]
    DIRECTION INPUT ;
    USE SIGNAL ;
    PORT
      LAYER M4 ;
        RECT 115.2600 96.8160 115.3440 96.8400 ;
    END
  END x_d[109]
  PIN x_d[10]
    DIRECTION INPUT ;
    USE SIGNAL ;
    PORT
      LAYER M4 ;
        RECT 115.2600 79.7760 115.3440 79.8000 ;
    END
  END x_d[10]
  PIN x_d[110]
    DIRECTION INPUT ;
    USE SIGNAL ;
    PORT
      LAYER M4 ;
        RECT 115.2600 96.9600 115.3440 96.9840 ;
    END
  END x_d[110]
  PIN x_d[111]
    DIRECTION INPUT ;
    USE SIGNAL ;
    PORT
      LAYER M4 ;
        RECT 115.2600 97.1520 115.3440 97.1760 ;
    END
  END x_d[111]
  PIN x_d[112]
    DIRECTION INPUT ;
    USE SIGNAL ;
    PORT
      LAYER M4 ;
        RECT 115.2600 97.3440 115.3440 97.3680 ;
    END
  END x_d[112]
  PIN x_d[113]
    DIRECTION INPUT ;
    USE SIGNAL ;
    PORT
      LAYER M4 ;
        RECT 115.2600 97.4880 115.3440 97.5120 ;
    END
  END x_d[113]
  PIN x_d[114]
    DIRECTION INPUT ;
    USE SIGNAL ;
    PORT
      LAYER M4 ;
        RECT 115.2600 97.6800 115.3440 97.7040 ;
    END
  END x_d[114]
  PIN x_d[115]
    DIRECTION INPUT ;
    USE SIGNAL ;
    PORT
      LAYER M4 ;
        RECT 115.2600 97.8720 115.3440 97.8960 ;
    END
  END x_d[115]
  PIN x_d[116]
    DIRECTION INPUT ;
    USE SIGNAL ;
    PORT
      LAYER M4 ;
        RECT 115.2600 97.9680 115.3440 97.9920 ;
    END
  END x_d[116]
  PIN x_d[117]
    DIRECTION INPUT ;
    USE SIGNAL ;
    PORT
      LAYER M4 ;
        RECT 115.2600 98.1600 115.3440 98.1840 ;
    END
  END x_d[117]
  PIN x_d[118]
    DIRECTION INPUT ;
    USE SIGNAL ;
    PORT
      LAYER M4 ;
        RECT 115.2600 98.3520 115.3440 98.3760 ;
    END
  END x_d[118]
  PIN x_d[119]
    DIRECTION INPUT ;
    USE SIGNAL ;
    PORT
      LAYER M4 ;
        RECT 115.2600 98.4960 115.3440 98.5200 ;
    END
  END x_d[119]
  PIN x_d[11]
    DIRECTION INPUT ;
    USE SIGNAL ;
    PORT
      LAYER M4 ;
        RECT 115.2600 79.9680 115.3440 79.9920 ;
    END
  END x_d[11]
  PIN x_d[120]
    DIRECTION INPUT ;
    USE SIGNAL ;
    PORT
      LAYER M4 ;
        RECT 115.2600 98.6880 115.3440 98.7120 ;
    END
  END x_d[120]
  PIN x_d[121]
    DIRECTION INPUT ;
    USE SIGNAL ;
    PORT
      LAYER M4 ;
        RECT 115.2600 98.8800 115.3440 98.9040 ;
    END
  END x_d[121]
  PIN x_d[122]
    DIRECTION INPUT ;
    USE SIGNAL ;
    PORT
      LAYER M4 ;
        RECT 115.2600 99.0240 115.3440 99.0480 ;
    END
  END x_d[122]
  PIN x_d[123]
    DIRECTION INPUT ;
    USE SIGNAL ;
    PORT
      LAYER M4 ;
        RECT 115.2600 99.2160 115.3440 99.2400 ;
    END
  END x_d[123]
  PIN x_d[124]
    DIRECTION INPUT ;
    USE SIGNAL ;
    PORT
      LAYER M4 ;
        RECT 115.2600 99.4080 115.3440 99.4320 ;
    END
  END x_d[124]
  PIN x_d[125]
    DIRECTION INPUT ;
    USE SIGNAL ;
    PORT
      LAYER M4 ;
        RECT 115.2600 99.6000 115.3440 99.6240 ;
    END
  END x_d[125]
  PIN x_d[126]
    DIRECTION INPUT ;
    USE SIGNAL ;
    PORT
      LAYER M4 ;
        RECT 115.2600 99.6960 115.3440 99.7200 ;
    END
  END x_d[126]
  PIN x_d[127]
    DIRECTION INPUT ;
    USE SIGNAL ;
    PORT
      LAYER M4 ;
        RECT 115.2600 99.8880 115.3440 99.9120 ;
    END
  END x_d[127]
  PIN x_d[12]
    DIRECTION INPUT ;
    USE SIGNAL ;
    PORT
      LAYER M4 ;
        RECT 115.2600 80.1600 115.3440 80.1840 ;
    END
  END x_d[12]
  PIN x_d[13]
    DIRECTION INPUT ;
    USE SIGNAL ;
    PORT
      LAYER M4 ;
        RECT 115.2600 80.3040 115.3440 80.3280 ;
    END
  END x_d[13]
  PIN x_d[14]
    DIRECTION INPUT ;
    USE SIGNAL ;
    PORT
      LAYER M4 ;
        RECT 115.2600 80.4960 115.3440 80.5200 ;
    END
  END x_d[14]
  PIN x_d[15]
    DIRECTION INPUT ;
    USE SIGNAL ;
    PORT
      LAYER M4 ;
        RECT 115.2600 80.6400 115.3440 80.6640 ;
    END
  END x_d[15]
  PIN x_d[16]
    DIRECTION INPUT ;
    USE SIGNAL ;
    PORT
      LAYER M4 ;
        RECT 115.2600 80.8320 115.3440 80.8560 ;
    END
  END x_d[16]
  PIN x_d[17]
    DIRECTION INPUT ;
    USE SIGNAL ;
    PORT
      LAYER M4 ;
        RECT 115.2600 80.9760 115.3440 81.0000 ;
    END
  END x_d[17]
  PIN x_d[18]
    DIRECTION INPUT ;
    USE SIGNAL ;
    PORT
      LAYER M4 ;
        RECT 115.2600 81.1680 115.3440 81.1920 ;
    END
  END x_d[18]
  PIN x_d[19]
    DIRECTION INPUT ;
    USE SIGNAL ;
    PORT
      LAYER M4 ;
        RECT 115.2600 81.3600 115.3440 81.3840 ;
    END
  END x_d[19]
  PIN x_d[1]
    DIRECTION INPUT ;
    USE SIGNAL ;
    PORT
      LAYER M4 ;
        RECT 115.2600 78.2400 115.3440 78.2640 ;
    END
  END x_d[1]
  PIN x_d[20]
    DIRECTION INPUT ;
    USE SIGNAL ;
    PORT
      LAYER M4 ;
        RECT 115.2600 81.5040 115.3440 81.5280 ;
    END
  END x_d[20]
  PIN x_d[21]
    DIRECTION INPUT ;
    USE SIGNAL ;
    PORT
      LAYER M4 ;
        RECT 115.2600 81.6960 115.3440 81.7200 ;
    END
  END x_d[21]
  PIN x_d[22]
    DIRECTION INPUT ;
    USE SIGNAL ;
    PORT
      LAYER M4 ;
        RECT 115.2600 81.8400 115.3440 81.8640 ;
    END
  END x_d[22]
  PIN x_d[23]
    DIRECTION INPUT ;
    USE SIGNAL ;
    PORT
      LAYER M4 ;
        RECT 115.2600 82.0320 115.3440 82.0560 ;
    END
  END x_d[23]
  PIN x_d[24]
    DIRECTION INPUT ;
    USE SIGNAL ;
    PORT
      LAYER M4 ;
        RECT 115.2600 82.1760 115.3440 82.2000 ;
    END
  END x_d[24]
  PIN x_d[25]
    DIRECTION INPUT ;
    USE SIGNAL ;
    PORT
      LAYER M4 ;
        RECT 115.2600 82.3680 115.3440 82.3920 ;
    END
  END x_d[25]
  PIN x_d[26]
    DIRECTION INPUT ;
    USE SIGNAL ;
    PORT
      LAYER M4 ;
        RECT 115.2600 82.5600 115.3440 82.5840 ;
    END
  END x_d[26]
  PIN x_d[27]
    DIRECTION INPUT ;
    USE SIGNAL ;
    PORT
      LAYER M4 ;
        RECT 115.2600 82.7040 115.3440 82.7280 ;
    END
  END x_d[27]
  PIN x_d[28]
    DIRECTION INPUT ;
    USE SIGNAL ;
    PORT
      LAYER M4 ;
        RECT 115.2600 82.8960 115.3440 82.9200 ;
    END
  END x_d[28]
  PIN x_d[29]
    DIRECTION INPUT ;
    USE SIGNAL ;
    PORT
      LAYER M4 ;
        RECT 115.2600 83.0400 115.3440 83.0640 ;
    END
  END x_d[29]
  PIN x_d[2]
    DIRECTION INPUT ;
    USE SIGNAL ;
    PORT
      LAYER M4 ;
        RECT 115.2600 78.4320 115.3440 78.4560 ;
    END
  END x_d[2]
  PIN x_d[30]
    DIRECTION INPUT ;
    USE SIGNAL ;
    PORT
      LAYER M4 ;
        RECT 115.2600 83.2320 115.3440 83.2560 ;
    END
  END x_d[30]
  PIN x_d[31]
    DIRECTION INPUT ;
    USE SIGNAL ;
    PORT
      LAYER M4 ;
        RECT 115.2600 83.4240 115.3440 83.4480 ;
    END
  END x_d[31]
  PIN x_d[32]
    DIRECTION INPUT ;
    USE SIGNAL ;
    PORT
      LAYER M4 ;
        RECT 115.2600 83.5680 115.3440 83.5920 ;
    END
  END x_d[32]
  PIN x_d[33]
    DIRECTION INPUT ;
    USE SIGNAL ;
    PORT
      LAYER M4 ;
        RECT 115.2600 83.7120 115.3440 83.7360 ;
    END
  END x_d[33]
  PIN x_d[34]
    DIRECTION INPUT ;
    USE SIGNAL ;
    PORT
      LAYER M4 ;
        RECT 115.2600 83.9040 115.3440 83.9280 ;
    END
  END x_d[34]
  PIN x_d[35]
    DIRECTION INPUT ;
    USE SIGNAL ;
    PORT
      LAYER M4 ;
        RECT 115.2600 84.0960 115.3440 84.1200 ;
    END
  END x_d[35]
  PIN x_d[36]
    DIRECTION INPUT ;
    USE SIGNAL ;
    PORT
      LAYER M4 ;
        RECT 115.2600 84.2880 115.3440 84.3120 ;
    END
  END x_d[36]
  PIN x_d[37]
    DIRECTION INPUT ;
    USE SIGNAL ;
    PORT
      LAYER M4 ;
        RECT 115.2600 84.4320 115.3440 84.4560 ;
    END
  END x_d[37]
  PIN x_d[38]
    DIRECTION INPUT ;
    USE SIGNAL ;
    PORT
      LAYER M4 ;
        RECT 115.2600 84.6240 115.3440 84.6480 ;
    END
  END x_d[38]
  PIN x_d[39]
    DIRECTION INPUT ;
    USE SIGNAL ;
    PORT
      LAYER M4 ;
        RECT 115.2600 84.8160 115.3440 84.8400 ;
    END
  END x_d[39]
  PIN x_d[3]
    DIRECTION INPUT ;
    USE SIGNAL ;
    PORT
      LAYER M4 ;
        RECT 115.2600 78.5760 115.3440 78.6000 ;
    END
  END x_d[3]
  PIN x_d[40]
    DIRECTION INPUT ;
    USE SIGNAL ;
    PORT
      LAYER M4 ;
        RECT 115.2600 84.9120 115.3440 84.9360 ;
    END
  END x_d[40]
  PIN x_d[41]
    DIRECTION INPUT ;
    USE SIGNAL ;
    PORT
      LAYER M4 ;
        RECT 115.2600 85.1040 115.3440 85.1280 ;
    END
  END x_d[41]
  PIN x_d[42]
    DIRECTION INPUT ;
    USE SIGNAL ;
    PORT
      LAYER M4 ;
        RECT 115.2600 85.2960 115.3440 85.3200 ;
    END
  END x_d[42]
  PIN x_d[43]
    DIRECTION INPUT ;
    USE SIGNAL ;
    PORT
      LAYER M4 ;
        RECT 115.2600 85.4400 115.3440 85.4640 ;
    END
  END x_d[43]
  PIN x_d[44]
    DIRECTION INPUT ;
    USE SIGNAL ;
    PORT
      LAYER M4 ;
        RECT 115.2600 85.6320 115.3440 85.6560 ;
    END
  END x_d[44]
  PIN x_d[45]
    DIRECTION INPUT ;
    USE SIGNAL ;
    PORT
      LAYER M4 ;
        RECT 115.2600 85.8240 115.3440 85.8480 ;
    END
  END x_d[45]
  PIN x_d[46]
    DIRECTION INPUT ;
    USE SIGNAL ;
    PORT
      LAYER M4 ;
        RECT 115.2600 85.9680 115.3440 85.9920 ;
    END
  END x_d[46]
  PIN x_d[47]
    DIRECTION INPUT ;
    USE SIGNAL ;
    PORT
      LAYER M4 ;
        RECT 115.2600 86.1600 115.3440 86.1840 ;
    END
  END x_d[47]
  PIN x_d[48]
    DIRECTION INPUT ;
    USE SIGNAL ;
    PORT
      LAYER M4 ;
        RECT 115.2600 86.3520 115.3440 86.3760 ;
    END
  END x_d[48]
  PIN x_d[49]
    DIRECTION INPUT ;
    USE SIGNAL ;
    PORT
      LAYER M4 ;
        RECT 115.2600 86.4480 115.3440 86.4720 ;
    END
  END x_d[49]
  PIN x_d[4]
    DIRECTION INPUT ;
    USE SIGNAL ;
    PORT
      LAYER M4 ;
        RECT 115.2600 78.7680 115.3440 78.7920 ;
    END
  END x_d[4]
  PIN x_d[50]
    DIRECTION INPUT ;
    USE SIGNAL ;
    PORT
      LAYER M4 ;
        RECT 115.2600 86.6400 115.3440 86.6640 ;
    END
  END x_d[50]
  PIN x_d[51]
    DIRECTION INPUT ;
    USE SIGNAL ;
    PORT
      LAYER M4 ;
        RECT 115.2600 86.8320 115.3440 86.8560 ;
    END
  END x_d[51]
  PIN x_d[52]
    DIRECTION INPUT ;
    USE SIGNAL ;
    PORT
      LAYER M4 ;
        RECT 115.2600 86.9760 115.3440 87.0000 ;
    END
  END x_d[52]
  PIN x_d[53]
    DIRECTION INPUT ;
    USE SIGNAL ;
    PORT
      LAYER M4 ;
        RECT 115.2600 87.1680 115.3440 87.1920 ;
    END
  END x_d[53]
  PIN x_d[54]
    DIRECTION INPUT ;
    USE SIGNAL ;
    PORT
      LAYER M4 ;
        RECT 115.2600 87.3600 115.3440 87.3840 ;
    END
  END x_d[54]
  PIN x_d[55]
    DIRECTION INPUT ;
    USE SIGNAL ;
    PORT
      LAYER M4 ;
        RECT 115.2600 87.5520 115.3440 87.5760 ;
    END
  END x_d[55]
  PIN x_d[56]
    DIRECTION INPUT ;
    USE SIGNAL ;
    PORT
      LAYER M4 ;
        RECT 115.2600 87.6960 115.3440 87.7200 ;
    END
  END x_d[56]
  PIN x_d[57]
    DIRECTION INPUT ;
    USE SIGNAL ;
    PORT
      LAYER M4 ;
        RECT 115.2600 87.8880 115.3440 87.9120 ;
    END
  END x_d[57]
  PIN x_d[58]
    DIRECTION INPUT ;
    USE SIGNAL ;
    PORT
      LAYER M4 ;
        RECT 115.2600 88.0800 115.3440 88.1040 ;
    END
  END x_d[58]
  PIN x_d[59]
    DIRECTION INPUT ;
    USE SIGNAL ;
    PORT
      LAYER M4 ;
        RECT 115.2600 88.1760 115.3440 88.2000 ;
    END
  END x_d[59]
  PIN x_d[5]
    DIRECTION INPUT ;
    USE SIGNAL ;
    PORT
      LAYER M4 ;
        RECT 115.2600 78.9120 115.3440 78.9360 ;
    END
  END x_d[5]
  PIN x_d[60]
    DIRECTION INPUT ;
    USE SIGNAL ;
    PORT
      LAYER M4 ;
        RECT 115.2600 88.3680 115.3440 88.3920 ;
    END
  END x_d[60]
  PIN x_d[61]
    DIRECTION INPUT ;
    USE SIGNAL ;
    PORT
      LAYER M4 ;
        RECT 115.2600 88.5600 115.3440 88.5840 ;
    END
  END x_d[61]
  PIN x_d[62]
    DIRECTION INPUT ;
    USE SIGNAL ;
    PORT
      LAYER M4 ;
        RECT 115.2600 88.7040 115.3440 88.7280 ;
    END
  END x_d[62]
  PIN x_d[63]
    DIRECTION INPUT ;
    USE SIGNAL ;
    PORT
      LAYER M4 ;
        RECT 115.2600 88.8960 115.3440 88.9200 ;
    END
  END x_d[63]
  PIN x_d[64]
    DIRECTION INPUT ;
    USE SIGNAL ;
    PORT
      LAYER M4 ;
        RECT 115.2600 89.0880 115.3440 89.1120 ;
    END
  END x_d[64]
  PIN x_d[65]
    DIRECTION INPUT ;
    USE SIGNAL ;
    PORT
      LAYER M4 ;
        RECT 115.2600 89.2320 115.3440 89.2560 ;
    END
  END x_d[65]
  PIN x_d[66]
    DIRECTION INPUT ;
    USE SIGNAL ;
    PORT
      LAYER M4 ;
        RECT 115.2600 89.4240 115.3440 89.4480 ;
    END
  END x_d[66]
  PIN x_d[67]
    DIRECTION INPUT ;
    USE SIGNAL ;
    PORT
      LAYER M4 ;
        RECT 115.2600 89.5680 115.3440 89.5920 ;
    END
  END x_d[67]
  PIN x_d[68]
    DIRECTION INPUT ;
    USE SIGNAL ;
    PORT
      LAYER M4 ;
        RECT 115.2600 89.7600 115.3440 89.7840 ;
    END
  END x_d[68]
  PIN x_d[69]
    DIRECTION INPUT ;
    USE SIGNAL ;
    PORT
      LAYER M4 ;
        RECT 115.2600 89.9520 115.3440 89.9760 ;
    END
  END x_d[69]
  PIN x_d[6]
    DIRECTION INPUT ;
    USE SIGNAL ;
    PORT
      LAYER M4 ;
        RECT 115.2600 79.1040 115.3440 79.1280 ;
    END
  END x_d[6]
  PIN x_d[70]
    DIRECTION INPUT ;
    USE SIGNAL ;
    PORT
      LAYER M4 ;
        RECT 115.2600 90.0960 115.3440 90.1200 ;
    END
  END x_d[70]
  PIN x_d[71]
    DIRECTION INPUT ;
    USE SIGNAL ;
    PORT
      LAYER M4 ;
        RECT 115.2600 90.2880 115.3440 90.3120 ;
    END
  END x_d[71]
  PIN x_d[72]
    DIRECTION INPUT ;
    USE SIGNAL ;
    PORT
      LAYER M4 ;
        RECT 115.2600 90.4320 115.3440 90.4560 ;
    END
  END x_d[72]
  PIN x_d[73]
    DIRECTION INPUT ;
    USE SIGNAL ;
    PORT
      LAYER M4 ;
        RECT 115.2600 90.6240 115.3440 90.6480 ;
    END
  END x_d[73]
  PIN x_d[74]
    DIRECTION INPUT ;
    USE SIGNAL ;
    PORT
      LAYER M4 ;
        RECT 115.2600 90.8160 115.3440 90.8400 ;
    END
  END x_d[74]
  PIN x_d[75]
    DIRECTION INPUT ;
    USE SIGNAL ;
    PORT
      LAYER M4 ;
        RECT 115.2600 90.9600 115.3440 90.9840 ;
    END
  END x_d[75]
  PIN x_d[76]
    DIRECTION INPUT ;
    USE SIGNAL ;
    PORT
      LAYER M4 ;
        RECT 115.2600 91.1520 115.3440 91.1760 ;
    END
  END x_d[76]
  PIN x_d[77]
    DIRECTION INPUT ;
    USE SIGNAL ;
    PORT
      LAYER M4 ;
        RECT 115.2600 91.2960 115.3440 91.3200 ;
    END
  END x_d[77]
  PIN x_d[78]
    DIRECTION INPUT ;
    USE SIGNAL ;
    PORT
      LAYER M4 ;
        RECT 115.2600 91.4880 115.3440 91.5120 ;
    END
  END x_d[78]
  PIN x_d[79]
    DIRECTION INPUT ;
    USE SIGNAL ;
    PORT
      LAYER M4 ;
        RECT 115.2600 91.6320 115.3440 91.6560 ;
    END
  END x_d[79]
  PIN x_d[7]
    DIRECTION INPUT ;
    USE SIGNAL ;
    PORT
      LAYER M4 ;
        RECT 115.2600 79.2960 115.3440 79.3200 ;
    END
  END x_d[7]
  PIN x_d[80]
    DIRECTION INPUT ;
    USE SIGNAL ;
    PORT
      LAYER M4 ;
        RECT 115.2600 91.8240 115.3440 91.8480 ;
    END
  END x_d[80]
  PIN x_d[81]
    DIRECTION INPUT ;
    USE SIGNAL ;
    PORT
      LAYER M4 ;
        RECT 115.2600 92.0160 115.3440 92.0400 ;
    END
  END x_d[81]
  PIN x_d[82]
    DIRECTION INPUT ;
    USE SIGNAL ;
    PORT
      LAYER M4 ;
        RECT 115.2600 92.1600 115.3440 92.1840 ;
    END
  END x_d[82]
  PIN x_d[83]
    DIRECTION INPUT ;
    USE SIGNAL ;
    PORT
      LAYER M4 ;
        RECT 115.2600 92.3520 115.3440 92.3760 ;
    END
  END x_d[83]
  PIN x_d[84]
    DIRECTION INPUT ;
    USE SIGNAL ;
    PORT
      LAYER M4 ;
        RECT 115.2600 92.4960 115.3440 92.5200 ;
    END
  END x_d[84]
  PIN x_d[85]
    DIRECTION INPUT ;
    USE SIGNAL ;
    PORT
      LAYER M4 ;
        RECT 115.2600 92.6880 115.3440 92.7120 ;
    END
  END x_d[85]
  PIN x_d[86]
    DIRECTION INPUT ;
    USE SIGNAL ;
    PORT
      LAYER M4 ;
        RECT 115.2600 92.8320 115.3440 92.8560 ;
    END
  END x_d[86]
  PIN x_d[87]
    DIRECTION INPUT ;
    USE SIGNAL ;
    PORT
      LAYER M4 ;
        RECT 115.2600 93.0240 115.3440 93.0480 ;
    END
  END x_d[87]
  PIN x_d[88]
    DIRECTION INPUT ;
    USE SIGNAL ;
    PORT
      LAYER M4 ;
        RECT 115.2600 93.2160 115.3440 93.2400 ;
    END
  END x_d[88]
  PIN x_d[89]
    DIRECTION INPUT ;
    USE SIGNAL ;
    PORT
      LAYER M4 ;
        RECT 115.2600 93.3600 115.3440 93.3840 ;
    END
  END x_d[89]
  PIN x_d[8]
    DIRECTION INPUT ;
    USE SIGNAL ;
    PORT
      LAYER M4 ;
        RECT 115.2600 79.4400 115.3440 79.4640 ;
    END
  END x_d[8]
  PIN x_d[90]
    DIRECTION INPUT ;
    USE SIGNAL ;
    PORT
      LAYER M4 ;
        RECT 115.2600 93.5520 115.3440 93.5760 ;
    END
  END x_d[90]
  PIN x_d[91]
    DIRECTION INPUT ;
    USE SIGNAL ;
    PORT
      LAYER M4 ;
        RECT 115.2600 93.6960 115.3440 93.7200 ;
    END
  END x_d[91]
  PIN x_d[92]
    DIRECTION INPUT ;
    USE SIGNAL ;
    PORT
      LAYER M4 ;
        RECT 115.2600 93.8880 115.3440 93.9120 ;
    END
  END x_d[92]
  PIN x_d[93]
    DIRECTION INPUT ;
    USE SIGNAL ;
    PORT
      LAYER M4 ;
        RECT 115.2600 94.0800 115.3440 94.1040 ;
    END
  END x_d[93]
  PIN x_d[94]
    DIRECTION INPUT ;
    USE SIGNAL ;
    PORT
      LAYER M4 ;
        RECT 115.2600 94.2240 115.3440 94.2480 ;
    END
  END x_d[94]
  PIN x_d[95]
    DIRECTION INPUT ;
    USE SIGNAL ;
    PORT
      LAYER M4 ;
        RECT 115.2600 94.4160 115.3440 94.4400 ;
    END
  END x_d[95]
  PIN x_d[96]
    DIRECTION INPUT ;
    USE SIGNAL ;
    PORT
      LAYER M4 ;
        RECT 115.2600 94.6080 115.3440 94.6320 ;
    END
  END x_d[96]
  PIN x_d[97]
    DIRECTION INPUT ;
    USE SIGNAL ;
    PORT
      LAYER M4 ;
        RECT 115.2600 94.7040 115.3440 94.7280 ;
    END
  END x_d[97]
  PIN x_d[98]
    DIRECTION INPUT ;
    USE SIGNAL ;
    PORT
      LAYER M4 ;
        RECT 115.2600 94.8960 115.3440 94.9200 ;
    END
  END x_d[98]
  PIN x_d[99]
    DIRECTION INPUT ;
    USE SIGNAL ;
    PORT
      LAYER M4 ;
        RECT 115.2600 95.0880 115.3440 95.1120 ;
    END
  END x_d[99]
  PIN x_d[9]
    DIRECTION INPUT ;
    USE SIGNAL ;
    PORT
      LAYER M4 ;
        RECT 115.2600 79.6320 115.3440 79.6560 ;
    END
  END x_d[9]
  PIN fault_q[0]
    DIRECTION OUTPUT ;
    USE SIGNAL ;
    PORT
      LAYER M5 ;
        RECT 10.3680 140.3160 10.3920 140.4000 ;
    END
  END fault_q[0]
  PIN fault_q[1]
    DIRECTION OUTPUT ;
    USE SIGNAL ;
    PORT
      LAYER M5 ;
        RECT 12.1440 140.3160 12.1680 140.4000 ;
    END
  END fault_q[1]
  PIN fault_q[2]
    DIRECTION OUTPUT ;
    USE SIGNAL ;
    PORT
      LAYER M5 ;
        RECT 13.7280 140.3160 13.7520 140.4000 ;
    END
  END fault_q[2]
  PIN fault_q[3]
    DIRECTION OUTPUT ;
    USE SIGNAL ;
    PORT
      LAYER M5 ;
        RECT 15.5040 140.3160 15.5280 140.4000 ;
    END
  END fault_q[3]
  PIN fault_q[4]
    DIRECTION OUTPUT ;
    USE SIGNAL ;
    PORT
      LAYER M5 ;
        RECT 16.8960 140.3160 16.9200 140.4000 ;
    END
  END fault_q[4]
  PIN fault_q[5]
    DIRECTION OUTPUT ;
    USE SIGNAL ;
    PORT
      LAYER M5 ;
        RECT 18.4800 140.3160 18.5040 140.4000 ;
    END
  END fault_q[5]
  PIN fault_q[6]
    DIRECTION OUTPUT ;
    USE SIGNAL ;
    PORT
      LAYER M5 ;
        RECT 20.0640 140.3160 20.0880 140.4000 ;
    END
  END fault_q[6]
  PIN fault_q[7]
    DIRECTION OUTPUT ;
    USE SIGNAL ;
    PORT
      LAYER M5 ;
        RECT 21.6480 140.3160 21.6720 140.4000 ;
    END
  END fault_q[7]
  PIN fault_q[8]
    DIRECTION OUTPUT ;
    USE SIGNAL ;
    PORT
      LAYER M5 ;
        RECT 23.2320 140.3160 23.2560 140.4000 ;
    END
  END fault_q[8]
  PIN fault_q[9]
    DIRECTION OUTPUT ;
    USE SIGNAL ;
    PORT
      LAYER M5 ;
        RECT 24.8160 140.3160 24.8400 140.4000 ;
    END
  END fault_q[9]
  PIN fault_q[10]
    DIRECTION OUTPUT ;
    USE SIGNAL ;
    PORT
      LAYER M5 ;
        RECT 26.4000 140.3160 26.4240 140.4000 ;
    END
  END fault_q[10]
  PIN fault_q[11]
    DIRECTION OUTPUT ;
    USE SIGNAL ;
    PORT
      LAYER M5 ;
        RECT 27.7920 140.3160 27.8160 140.4000 ;
    END
  END fault_q[11]
  PIN fault_q[12]
    DIRECTION OUTPUT ;
    USE SIGNAL ;
    PORT
      LAYER M5 ;
        RECT 29.5680 140.3160 29.5920 140.4000 ;
    END
  END fault_q[12]
  PIN fault_q[13]
    DIRECTION OUTPUT ;
    USE SIGNAL ;
    PORT
      LAYER M5 ;
        RECT 31.1520 140.3160 31.1760 140.4000 ;
    END
  END fault_q[13]
  PIN fault_q[14]
    DIRECTION OUTPUT ;
    USE SIGNAL ;
    PORT
      LAYER M5 ;
        RECT 32.7360 140.3160 32.7600 140.4000 ;
    END
  END fault_q[14]
  PIN fault_q[15]
    DIRECTION OUTPUT ;
    USE SIGNAL ;
    PORT
      LAYER M5 ;
        RECT 34.3200 140.3160 34.3440 140.4000 ;
    END
  END fault_q[15]
  PIN fault_q[16]
    DIRECTION OUTPUT ;
    USE SIGNAL ;
    PORT
      LAYER M5 ;
        RECT 35.9040 140.3160 35.9280 140.4000 ;
    END
  END fault_q[16]
  PIN fault_q[17]
    DIRECTION OUTPUT ;
    USE SIGNAL ;
    PORT
      LAYER M5 ;
        RECT 37.4880 140.3160 37.5120 140.4000 ;
    END
  END fault_q[17]
  PIN fault_q[18]
    DIRECTION OUTPUT ;
    USE SIGNAL ;
    PORT
      LAYER M5 ;
        RECT 39.0720 140.3160 39.0960 140.4000 ;
    END
  END fault_q[18]
  PIN fault_q[19]
    DIRECTION OUTPUT ;
    USE SIGNAL ;
    PORT
      LAYER M5 ;
        RECT 40.6560 140.3160 40.6800 140.4000 ;
    END
  END fault_q[19]
  PIN fault_q[20]
    DIRECTION OUTPUT ;
    USE SIGNAL ;
    PORT
      LAYER M5 ;
        RECT 42.2400 140.3160 42.2640 140.4000 ;
    END
  END fault_q[20]
  PIN fault_q[21]
    DIRECTION OUTPUT ;
    USE SIGNAL ;
    PORT
      LAYER M5 ;
        RECT 43.8240 140.3160 43.8480 140.4000 ;
    END
  END fault_q[21]
  PIN fault_q[22]
    DIRECTION OUTPUT ;
    USE SIGNAL ;
    PORT
      LAYER M5 ;
        RECT 45.0240 140.3160 45.0480 140.4000 ;
    END
  END fault_q[22]
  PIN fault_q[23]
    DIRECTION OUTPUT ;
    USE SIGNAL ;
    PORT
      LAYER M5 ;
        RECT 46.9920 140.3160 47.0160 140.4000 ;
    END
  END fault_q[23]
  PIN fault_q[24]
    DIRECTION OUTPUT ;
    USE SIGNAL ;
    PORT
      LAYER M5 ;
        RECT 48.5760 140.3160 48.6000 140.4000 ;
    END
  END fault_q[24]
  PIN fault_q[25]
    DIRECTION OUTPUT ;
    USE SIGNAL ;
    PORT
      LAYER M5 ;
        RECT 50.1600 140.3160 50.1840 140.4000 ;
    END
  END fault_q[25]
  PIN fault_q[26]
    DIRECTION OUTPUT ;
    USE SIGNAL ;
    PORT
      LAYER M5 ;
        RECT 51.7440 140.3160 51.7680 140.4000 ;
    END
  END fault_q[26]
  PIN fault_q[27]
    DIRECTION OUTPUT ;
    USE SIGNAL ;
    PORT
      LAYER M5 ;
        RECT 53.3280 140.3160 53.3520 140.4000 ;
    END
  END fault_q[27]
  PIN fault_q[28]
    DIRECTION OUTPUT ;
    USE SIGNAL ;
    PORT
      LAYER M5 ;
        RECT 54.9120 140.3160 54.9360 140.4000 ;
    END
  END fault_q[28]
  PIN fault_q[29]
    DIRECTION OUTPUT ;
    USE SIGNAL ;
    PORT
      LAYER M5 ;
        RECT 56.4960 140.3160 56.5200 140.4000 ;
    END
  END fault_q[29]
  PIN fault_q[30]
    DIRECTION OUTPUT ;
    USE SIGNAL ;
    PORT
      LAYER M5 ;
        RECT 57.8880 140.3160 57.9120 140.4000 ;
    END
  END fault_q[30]
  PIN fault_q[31]
    DIRECTION OUTPUT ;
    USE SIGNAL ;
    PORT
      LAYER M5 ;
        RECT 59.6640 140.3160 59.6880 140.4000 ;
    END
  END fault_q[31]
  PIN fault_q[32]
    DIRECTION OUTPUT ;
    USE SIGNAL ;
    PORT
      LAYER M5 ;
        RECT 61.2480 140.3160 61.2720 140.4000 ;
    END
  END fault_q[32]
  PIN fault_q[33]
    DIRECTION OUTPUT ;
    USE SIGNAL ;
    PORT
      LAYER M5 ;
        RECT 63.0240 140.3160 63.0480 140.4000 ;
    END
  END fault_q[33]
  PIN fault_q[34]
    DIRECTION OUTPUT ;
    USE SIGNAL ;
    PORT
      LAYER M5 ;
        RECT 64.4160 140.3160 64.4400 140.4000 ;
    END
  END fault_q[34]
  PIN fault_q[35]
    DIRECTION OUTPUT ;
    USE SIGNAL ;
    PORT
      LAYER M5 ;
        RECT 66.0000 140.3160 66.0240 140.4000 ;
    END
  END fault_q[35]
  PIN fault_q[36]
    DIRECTION OUTPUT ;
    USE SIGNAL ;
    PORT
      LAYER M5 ;
        RECT 67.5840 140.3160 67.6080 140.4000 ;
    END
  END fault_q[36]
  PIN fault_q[37]
    DIRECTION OUTPUT ;
    USE SIGNAL ;
    PORT
      LAYER M5 ;
        RECT 69.1680 140.3160 69.1920 140.4000 ;
    END
  END fault_q[37]
  PIN fault_q[38]
    DIRECTION OUTPUT ;
    USE SIGNAL ;
    PORT
      LAYER M5 ;
        RECT 70.7520 140.3160 70.7760 140.4000 ;
    END
  END fault_q[38]
  PIN fault_q[39]
    DIRECTION OUTPUT ;
    USE SIGNAL ;
    PORT
      LAYER M5 ;
        RECT 72.3360 140.3160 72.3600 140.4000 ;
    END
  END fault_q[39]
  PIN fault_q[40]
    DIRECTION OUTPUT ;
    USE SIGNAL ;
    PORT
      LAYER M5 ;
        RECT 73.9200 140.3160 73.9440 140.4000 ;
    END
  END fault_q[40]
  PIN fault_q[41]
    DIRECTION OUTPUT ;
    USE SIGNAL ;
    PORT
      LAYER M5 ;
        RECT 75.3120 140.3160 75.3360 140.4000 ;
    END
  END fault_q[41]
  PIN fault_q[42]
    DIRECTION OUTPUT ;
    USE SIGNAL ;
    PORT
      LAYER M5 ;
        RECT 77.0880 140.3160 77.1120 140.4000 ;
    END
  END fault_q[42]
  PIN fault_q[43]
    DIRECTION OUTPUT ;
    USE SIGNAL ;
    PORT
      LAYER M5 ;
        RECT 78.6720 140.3160 78.6960 140.4000 ;
    END
  END fault_q[43]
  PIN fault_q[44]
    DIRECTION OUTPUT ;
    USE SIGNAL ;
    PORT
      LAYER M5 ;
        RECT 80.2560 140.3160 80.2800 140.4000 ;
    END
  END fault_q[44]
  PIN fault_q[45]
    DIRECTION OUTPUT ;
    USE SIGNAL ;
    PORT
      LAYER M5 ;
        RECT 81.8400 140.3160 81.8640 140.4000 ;
    END
  END fault_q[45]
  PIN fault_q[46]
    DIRECTION OUTPUT ;
    USE SIGNAL ;
    PORT
      LAYER M5 ;
        RECT 83.4240 140.3160 83.4480 140.4000 ;
    END
  END fault_q[46]
  PIN fault_q[47]
    DIRECTION OUTPUT ;
    USE SIGNAL ;
    PORT
      LAYER M5 ;
        RECT 85.0080 140.3160 85.0320 140.4000 ;
    END
  END fault_q[47]
  PIN fault_q[48]
    DIRECTION OUTPUT ;
    USE SIGNAL ;
    PORT
      LAYER M5 ;
        RECT 86.5920 140.3160 86.6160 140.4000 ;
    END
  END fault_q[48]
  PIN fault_q[49]
    DIRECTION OUTPUT ;
    USE SIGNAL ;
    PORT
      LAYER M5 ;
        RECT 88.1760 140.3160 88.2000 140.4000 ;
    END
  END fault_q[49]
  OBS
    LAYER M1 ;
      RECT 0 0 115.344 140.4 ;
    LAYER M2 ;
      RECT 0 0 115.344 140.4 ;
    LAYER M3 ;
      RECT 0 0 115.344 140.4 ;
    LAYER M4 ;
      RECT 0.5 0.5 114.844 139.9 ;
    LAYER M5 ;
      RECT 0.5 0.5 114.844 139.9 ;
  END
END ot_qwen_tile_lsl_rawfault_m3
END LIBRARY
